VERSION 5.7 ;
  NOWIREEXTENSIONATPIN ON ;
  DIVIDERCHAR "/" ;
  BUSBITCHARS "[]" ;
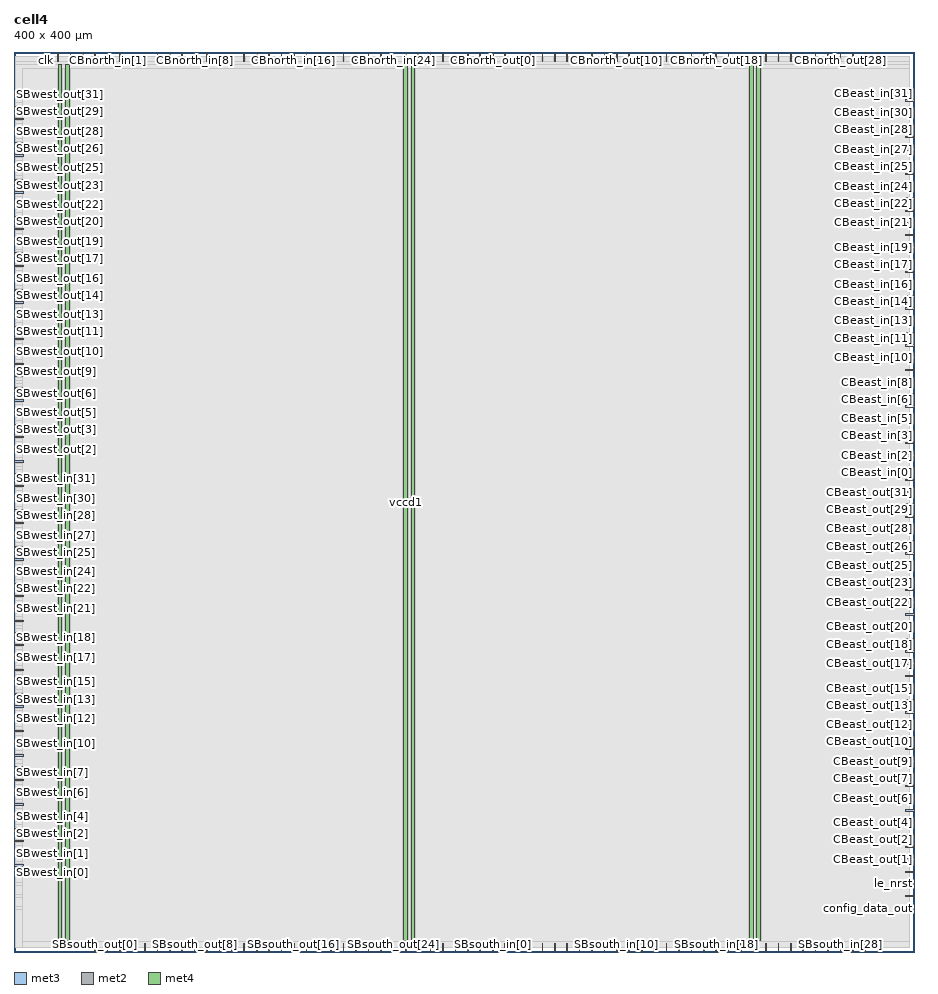
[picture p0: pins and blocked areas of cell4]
MACRO cell4
  CLASS BLOCK ;
  FOREIGN cell4 ;
  ORIGIN 0.000 0.000 ;
  SIZE 400.000 BY 400.000 ;
  PIN CBeast_in[0]
    DIRECTION INPUT ;
    USE SIGNAL ;
    ANTENNAGATEAREA 0.647700 ;
    ANTENNADIFFAREA 0.434700 ;
    PORT
      LAYER met3 ;
        RECT 396.000 209.480 400.000 210.080 ;
    END
  END CBeast_in[0]
  PIN CBeast_in[10]
    DIRECTION INPUT ;
    USE SIGNAL ;
    ANTENNAGATEAREA 0.647700 ;
    ANTENNADIFFAREA 0.434700 ;
    PORT
      LAYER met3 ;
        RECT 396.000 263.880 400.000 264.480 ;
    END
  END CBeast_in[10]
  PIN CBeast_in[11]
    DIRECTION INPUT ;
    USE SIGNAL ;
    ANTENNAGATEAREA 1.082400 ;
    ANTENNADIFFAREA 0.869400 ;
    PORT
      LAYER met3 ;
        RECT 396.000 269.320 400.000 269.920 ;
    END
  END CBeast_in[11]
  PIN CBeast_in[12]
    DIRECTION INPUT ;
    USE SIGNAL ;
    ANTENNAGATEAREA 0.647700 ;
    ANTENNADIFFAREA 0.434700 ;
    PORT
      LAYER met3 ;
        RECT 396.000 274.760 400.000 275.360 ;
    END
  END CBeast_in[12]
  PIN CBeast_in[13]
    DIRECTION INPUT ;
    USE SIGNAL ;
    ANTENNAGATEAREA 0.647700 ;
    ANTENNADIFFAREA 0.434700 ;
    PORT
      LAYER met3 ;
        RECT 396.000 280.200 400.000 280.800 ;
    END
  END CBeast_in[13]
  PIN CBeast_in[14]
    DIRECTION INPUT ;
    USE SIGNAL ;
    ANTENNAGATEAREA 0.647700 ;
    ANTENNADIFFAREA 0.434700 ;
    PORT
      LAYER met3 ;
        RECT 396.000 285.640 400.000 286.240 ;
    END
  END CBeast_in[14]
  PIN CBeast_in[15]
    DIRECTION INPUT ;
    USE SIGNAL ;
    ANTENNAGATEAREA 0.647700 ;
    ANTENNADIFFAREA 0.434700 ;
    PORT
      LAYER met3 ;
        RECT 396.000 291.080 400.000 291.680 ;
    END
  END CBeast_in[15]
  PIN CBeast_in[16]
    DIRECTION INPUT ;
    USE SIGNAL ;
    ANTENNAGATEAREA 1.028400 ;
    ANTENNADIFFAREA 0.869400 ;
    PORT
      LAYER met3 ;
        RECT 396.000 296.520 400.000 297.120 ;
    END
  END CBeast_in[16]
  PIN CBeast_in[17]
    DIRECTION INPUT ;
    USE SIGNAL ;
    ANTENNAGATEAREA 0.593700 ;
    ANTENNADIFFAREA 0.434700 ;
    PORT
      LAYER met3 ;
        RECT 396.000 301.960 400.000 302.560 ;
    END
  END CBeast_in[17]
  PIN CBeast_in[18]
    DIRECTION INPUT ;
    USE SIGNAL ;
    ANTENNAGATEAREA 0.593700 ;
    ANTENNADIFFAREA 0.434700 ;
    PORT
      LAYER met3 ;
        RECT 396.000 307.400 400.000 308.000 ;
    END
  END CBeast_in[18]
  PIN CBeast_in[19]
    DIRECTION INPUT ;
    USE SIGNAL ;
    ANTENNAGATEAREA 0.593700 ;
    ANTENNADIFFAREA 0.434700 ;
    PORT
      LAYER met3 ;
        RECT 396.000 312.840 400.000 313.440 ;
    END
  END CBeast_in[19]
  PIN CBeast_in[1]
    DIRECTION INPUT ;
    USE SIGNAL ;
    ANTENNAGATEAREA 0.647700 ;
    ANTENNADIFFAREA 0.434700 ;
    PORT
      LAYER met3 ;
        RECT 396.000 214.920 400.000 215.520 ;
    END
  END CBeast_in[1]
  PIN CBeast_in[20]
    DIRECTION INPUT ;
    USE SIGNAL ;
    ANTENNAGATEAREA 0.647700 ;
    ANTENNADIFFAREA 0.434700 ;
    PORT
      LAYER met3 ;
        RECT 396.000 318.280 400.000 318.880 ;
    END
  END CBeast_in[20]
  PIN CBeast_in[21]
    DIRECTION INPUT ;
    USE SIGNAL ;
    ANTENNAGATEAREA 0.647700 ;
    ANTENNADIFFAREA 0.434700 ;
    PORT
      LAYER met3 ;
        RECT 396.000 323.720 400.000 324.320 ;
    END
  END CBeast_in[21]
  PIN CBeast_in[22]
    DIRECTION INPUT ;
    USE SIGNAL ;
    ANTENNAGATEAREA 0.593700 ;
    ANTENNADIFFAREA 0.434700 ;
    PORT
      LAYER met3 ;
        RECT 396.000 329.160 400.000 329.760 ;
    END
  END CBeast_in[22]
  PIN CBeast_in[23]
    DIRECTION INPUT ;
    USE SIGNAL ;
    ANTENNAGATEAREA 1.082400 ;
    ANTENNADIFFAREA 0.869400 ;
    PORT
      LAYER met3 ;
        RECT 396.000 334.600 400.000 335.200 ;
    END
  END CBeast_in[23]
  PIN CBeast_in[24]
    DIRECTION INPUT ;
    USE SIGNAL ;
    ANTENNAGATEAREA 0.647700 ;
    ANTENNADIFFAREA 0.434700 ;
    PORT
      LAYER met3 ;
        RECT 396.000 340.040 400.000 340.640 ;
    END
  END CBeast_in[24]
  PIN CBeast_in[25]
    DIRECTION INPUT ;
    USE SIGNAL ;
    ANTENNAGATEAREA 0.647700 ;
    ANTENNADIFFAREA 0.434700 ;
    PORT
      LAYER met3 ;
        RECT 396.000 345.480 400.000 346.080 ;
    END
  END CBeast_in[25]
  PIN CBeast_in[26]
    DIRECTION INPUT ;
    USE SIGNAL ;
    ANTENNAGATEAREA 0.647700 ;
    ANTENNADIFFAREA 0.434700 ;
    PORT
      LAYER met3 ;
        RECT 396.000 350.920 400.000 351.520 ;
    END
  END CBeast_in[26]
  PIN CBeast_in[27]
    DIRECTION INPUT ;
    USE SIGNAL ;
    ANTENNAGATEAREA 0.593700 ;
    ANTENNADIFFAREA 0.434700 ;
    PORT
      LAYER met3 ;
        RECT 396.000 356.360 400.000 356.960 ;
    END
  END CBeast_in[27]
  PIN CBeast_in[28]
    DIRECTION INPUT ;
    USE SIGNAL ;
    ANTENNAGATEAREA 0.593700 ;
    ANTENNADIFFAREA 0.434700 ;
    PORT
      LAYER met3 ;
        RECT 396.000 361.800 400.000 362.400 ;
    END
  END CBeast_in[28]
  PIN CBeast_in[29]
    DIRECTION INPUT ;
    USE SIGNAL ;
    ANTENNAGATEAREA 0.593700 ;
    ANTENNADIFFAREA 0.434700 ;
    PORT
      LAYER met3 ;
        RECT 396.000 367.240 400.000 367.840 ;
    END
  END CBeast_in[29]
  PIN CBeast_in[2]
    DIRECTION INPUT ;
    USE SIGNAL ;
    ANTENNAGATEAREA 0.647700 ;
    ANTENNADIFFAREA 0.434700 ;
    PORT
      LAYER met3 ;
        RECT 396.000 220.360 400.000 220.960 ;
    END
  END CBeast_in[2]
  PIN CBeast_in[30]
    DIRECTION INPUT ;
    USE SIGNAL ;
    ANTENNAGATEAREA 0.647700 ;
    ANTENNADIFFAREA 0.434700 ;
    PORT
      LAYER met3 ;
        RECT 396.000 372.680 400.000 373.280 ;
    END
  END CBeast_in[30]
  PIN CBeast_in[31]
    DIRECTION INPUT ;
    USE SIGNAL ;
    ANTENNAGATEAREA 0.593700 ;
    ANTENNADIFFAREA 0.434700 ;
    PORT
      LAYER met3 ;
        RECT 396.000 378.120 400.000 378.720 ;
    END
  END CBeast_in[31]
  PIN CBeast_in[3]
    DIRECTION INPUT ;
    USE SIGNAL ;
    ANTENNAGATEAREA 0.647700 ;
    ANTENNADIFFAREA 0.434700 ;
    PORT
      LAYER met3 ;
        RECT 396.000 225.800 400.000 226.400 ;
    END
  END CBeast_in[3]
  PIN CBeast_in[4]
    DIRECTION INPUT ;
    USE SIGNAL ;
    ANTENNAGATEAREA 0.647700 ;
    ANTENNADIFFAREA 0.434700 ;
    PORT
      LAYER met3 ;
        RECT 396.000 231.240 400.000 231.840 ;
    END
  END CBeast_in[4]
  PIN CBeast_in[5]
    DIRECTION INPUT ;
    USE SIGNAL ;
    ANTENNAGATEAREA 0.647700 ;
    ANTENNADIFFAREA 0.434700 ;
    PORT
      LAYER met3 ;
        RECT 396.000 236.680 400.000 237.280 ;
    END
  END CBeast_in[5]
  PIN CBeast_in[6]
    DIRECTION INPUT ;
    USE SIGNAL ;
    ANTENNAGATEAREA 0.647700 ;
    ANTENNADIFFAREA 0.434700 ;
    PORT
      LAYER met3 ;
        RECT 396.000 242.120 400.000 242.720 ;
    END
  END CBeast_in[6]
  PIN CBeast_in[7]
    DIRECTION INPUT ;
    USE SIGNAL ;
    ANTENNAGATEAREA 0.647700 ;
    ANTENNADIFFAREA 0.434700 ;
    PORT
      LAYER met3 ;
        RECT 396.000 247.560 400.000 248.160 ;
    END
  END CBeast_in[7]
  PIN CBeast_in[8]
    DIRECTION INPUT ;
    USE SIGNAL ;
    ANTENNAGATEAREA 0.647700 ;
    ANTENNADIFFAREA 0.434700 ;
    PORT
      LAYER met3 ;
        RECT 396.000 253.000 400.000 253.600 ;
    END
  END CBeast_in[8]
  PIN CBeast_in[9]
    DIRECTION INPUT ;
    USE SIGNAL ;
    ANTENNAGATEAREA 0.647700 ;
    ANTENNADIFFAREA 0.434700 ;
    PORT
      LAYER met3 ;
        RECT 396.000 258.440 400.000 259.040 ;
    END
  END CBeast_in[9]
  PIN CBeast_out[0]
    DIRECTION OUTPUT ;
    USE SIGNAL ;
    ANTENNADIFFAREA 0.445500 ;
    PORT
      LAYER met3 ;
        RECT 396.000 35.400 400.000 36.000 ;
    END
  END CBeast_out[0]
  PIN CBeast_out[10]
    DIRECTION OUTPUT ;
    USE SIGNAL ;
    ANTENNADIFFAREA 0.445500 ;
    PORT
      LAYER met3 ;
        RECT 396.000 89.800 400.000 90.400 ;
    END
  END CBeast_out[10]
  PIN CBeast_out[11]
    DIRECTION OUTPUT ;
    USE SIGNAL ;
    ANTENNADIFFAREA 0.445500 ;
    PORT
      LAYER met3 ;
        RECT 396.000 95.240 400.000 95.840 ;
    END
  END CBeast_out[11]
  PIN CBeast_out[12]
    DIRECTION OUTPUT ;
    USE SIGNAL ;
    ANTENNADIFFAREA 0.445500 ;
    PORT
      LAYER met3 ;
        RECT 396.000 100.680 400.000 101.280 ;
    END
  END CBeast_out[12]
  PIN CBeast_out[13]
    DIRECTION OUTPUT ;
    USE SIGNAL ;
    ANTENNADIFFAREA 0.445500 ;
    PORT
      LAYER met3 ;
        RECT 396.000 106.120 400.000 106.720 ;
    END
  END CBeast_out[13]
  PIN CBeast_out[14]
    DIRECTION OUTPUT ;
    USE SIGNAL ;
    ANTENNADIFFAREA 0.445500 ;
    PORT
      LAYER met3 ;
        RECT 396.000 111.560 400.000 112.160 ;
    END
  END CBeast_out[14]
  PIN CBeast_out[15]
    DIRECTION OUTPUT ;
    USE SIGNAL ;
    ANTENNADIFFAREA 0.445500 ;
    PORT
      LAYER met3 ;
        RECT 396.000 117.000 400.000 117.600 ;
    END
  END CBeast_out[15]
  PIN CBeast_out[16]
    DIRECTION OUTPUT ;
    USE SIGNAL ;
    ANTENNADIFFAREA 0.445500 ;
    PORT
      LAYER met3 ;
        RECT 396.000 122.440 400.000 123.040 ;
    END
  END CBeast_out[16]
  PIN CBeast_out[17]
    DIRECTION OUTPUT ;
    USE SIGNAL ;
    ANTENNADIFFAREA 0.445500 ;
    PORT
      LAYER met3 ;
        RECT 396.000 127.880 400.000 128.480 ;
    END
  END CBeast_out[17]
  PIN CBeast_out[18]
    DIRECTION OUTPUT ;
    USE SIGNAL ;
    ANTENNADIFFAREA 0.445500 ;
    PORT
      LAYER met3 ;
        RECT 396.000 133.320 400.000 133.920 ;
    END
  END CBeast_out[18]
  PIN CBeast_out[19]
    DIRECTION OUTPUT ;
    USE SIGNAL ;
    ANTENNADIFFAREA 0.445500 ;
    PORT
      LAYER met3 ;
        RECT 396.000 138.760 400.000 139.360 ;
    END
  END CBeast_out[19]
  PIN CBeast_out[1]
    DIRECTION OUTPUT ;
    USE SIGNAL ;
    ANTENNADIFFAREA 0.445500 ;
    PORT
      LAYER met3 ;
        RECT 396.000 40.840 400.000 41.440 ;
    END
  END CBeast_out[1]
  PIN CBeast_out[20]
    DIRECTION OUTPUT ;
    USE SIGNAL ;
    ANTENNADIFFAREA 0.445500 ;
    PORT
      LAYER met3 ;
        RECT 396.000 144.200 400.000 144.800 ;
    END
  END CBeast_out[20]
  PIN CBeast_out[21]
    DIRECTION OUTPUT ;
    USE SIGNAL ;
    ANTENNADIFFAREA 0.445500 ;
    PORT
      LAYER met3 ;
        RECT 396.000 149.640 400.000 150.240 ;
    END
  END CBeast_out[21]
  PIN CBeast_out[22]
    DIRECTION OUTPUT ;
    USE SIGNAL ;
    ANTENNADIFFAREA 0.445500 ;
    PORT
      LAYER met3 ;
        RECT 396.000 155.080 400.000 155.680 ;
    END
  END CBeast_out[22]
  PIN CBeast_out[23]
    DIRECTION OUTPUT ;
    USE SIGNAL ;
    ANTENNADIFFAREA 0.445500 ;
    PORT
      LAYER met3 ;
        RECT 396.000 160.520 400.000 161.120 ;
    END
  END CBeast_out[23]
  PIN CBeast_out[24]
    DIRECTION OUTPUT ;
    USE SIGNAL ;
    ANTENNADIFFAREA 0.445500 ;
    PORT
      LAYER met3 ;
        RECT 396.000 165.960 400.000 166.560 ;
    END
  END CBeast_out[24]
  PIN CBeast_out[25]
    DIRECTION OUTPUT ;
    USE SIGNAL ;
    ANTENNADIFFAREA 0.445500 ;
    PORT
      LAYER met3 ;
        RECT 396.000 171.400 400.000 172.000 ;
    END
  END CBeast_out[25]
  PIN CBeast_out[26]
    DIRECTION OUTPUT ;
    USE SIGNAL ;
    ANTENNADIFFAREA 0.445500 ;
    PORT
      LAYER met3 ;
        RECT 396.000 176.840 400.000 177.440 ;
    END
  END CBeast_out[26]
  PIN CBeast_out[27]
    DIRECTION OUTPUT ;
    USE SIGNAL ;
    ANTENNADIFFAREA 0.445500 ;
    PORT
      LAYER met3 ;
        RECT 396.000 182.280 400.000 182.880 ;
    END
  END CBeast_out[27]
  PIN CBeast_out[28]
    DIRECTION OUTPUT ;
    USE SIGNAL ;
    ANTENNADIFFAREA 0.445500 ;
    PORT
      LAYER met3 ;
        RECT 396.000 187.720 400.000 188.320 ;
    END
  END CBeast_out[28]
  PIN CBeast_out[29]
    DIRECTION OUTPUT ;
    USE SIGNAL ;
    ANTENNADIFFAREA 0.445500 ;
    PORT
      LAYER met3 ;
        RECT 396.000 193.160 400.000 193.760 ;
    END
  END CBeast_out[29]
  PIN CBeast_out[2]
    DIRECTION OUTPUT ;
    USE SIGNAL ;
    ANTENNADIFFAREA 0.445500 ;
    PORT
      LAYER met3 ;
        RECT 396.000 46.280 400.000 46.880 ;
    END
  END CBeast_out[2]
  PIN CBeast_out[30]
    DIRECTION OUTPUT ;
    USE SIGNAL ;
    ANTENNADIFFAREA 0.445500 ;
    PORT
      LAYER met3 ;
        RECT 396.000 198.600 400.000 199.200 ;
    END
  END CBeast_out[30]
  PIN CBeast_out[31]
    DIRECTION OUTPUT ;
    USE SIGNAL ;
    ANTENNADIFFAREA 0.445500 ;
    PORT
      LAYER met3 ;
        RECT 396.000 204.040 400.000 204.640 ;
    END
  END CBeast_out[31]
  PIN CBeast_out[3]
    DIRECTION OUTPUT ;
    USE SIGNAL ;
    ANTENNADIFFAREA 0.445500 ;
    PORT
      LAYER met3 ;
        RECT 396.000 51.720 400.000 52.320 ;
    END
  END CBeast_out[3]
  PIN CBeast_out[4]
    DIRECTION OUTPUT ;
    USE SIGNAL ;
    ANTENNADIFFAREA 0.445500 ;
    PORT
      LAYER met3 ;
        RECT 396.000 57.160 400.000 57.760 ;
    END
  END CBeast_out[4]
  PIN CBeast_out[5]
    DIRECTION OUTPUT ;
    USE SIGNAL ;
    ANTENNADIFFAREA 0.445500 ;
    PORT
      LAYER met3 ;
        RECT 396.000 62.600 400.000 63.200 ;
    END
  END CBeast_out[5]
  PIN CBeast_out[6]
    DIRECTION OUTPUT ;
    USE SIGNAL ;
    ANTENNADIFFAREA 0.445500 ;
    PORT
      LAYER met3 ;
        RECT 396.000 68.040 400.000 68.640 ;
    END
  END CBeast_out[6]
  PIN CBeast_out[7]
    DIRECTION OUTPUT ;
    USE SIGNAL ;
    ANTENNADIFFAREA 0.445500 ;
    PORT
      LAYER met3 ;
        RECT 396.000 73.480 400.000 74.080 ;
    END
  END CBeast_out[7]
  PIN CBeast_out[8]
    DIRECTION OUTPUT ;
    USE SIGNAL ;
    ANTENNADIFFAREA 0.445500 ;
    PORT
      LAYER met3 ;
        RECT 396.000 78.920 400.000 79.520 ;
    END
  END CBeast_out[8]
  PIN CBeast_out[9]
    DIRECTION OUTPUT ;
    USE SIGNAL ;
    ANTENNADIFFAREA 0.445500 ;
    PORT
      LAYER met3 ;
        RECT 396.000 84.360 400.000 84.960 ;
    END
  END CBeast_out[9]
  PIN CBnorth_in[0]
    DIRECTION INPUT ;
    USE SIGNAL ;
    ANTENNAGATEAREA 0.593700 ;
    ANTENNADIFFAREA 0.434700 ;
    PORT
      LAYER met2 ;
        RECT 35.970 396.000 36.250 400.000 ;
    END
  END CBnorth_in[0]
  PIN CBnorth_in[10]
    DIRECTION INPUT ;
    USE SIGNAL ;
    ANTENNAGATEAREA 0.593700 ;
    ANTENNADIFFAREA 0.434700 ;
    PORT
      LAYER met2 ;
        RECT 91.170 396.000 91.450 400.000 ;
    END
  END CBnorth_in[10]
  PIN CBnorth_in[11]
    DIRECTION INPUT ;
    USE SIGNAL ;
    ANTENNAGATEAREA 1.028400 ;
    ANTENNADIFFAREA 0.869400 ;
    PORT
      LAYER met2 ;
        RECT 96.690 396.000 96.970 400.000 ;
    END
  END CBnorth_in[11]
  PIN CBnorth_in[12]
    DIRECTION INPUT ;
    USE SIGNAL ;
    ANTENNAGATEAREA 0.593700 ;
    ANTENNADIFFAREA 0.434700 ;
    PORT
      LAYER met2 ;
        RECT 102.210 396.000 102.490 400.000 ;
    END
  END CBnorth_in[12]
  PIN CBnorth_in[13]
    DIRECTION INPUT ;
    USE SIGNAL ;
    ANTENNAGATEAREA 0.593700 ;
    ANTENNADIFFAREA 0.434700 ;
    PORT
      LAYER met2 ;
        RECT 107.730 396.000 108.010 400.000 ;
    END
  END CBnorth_in[13]
  PIN CBnorth_in[14]
    DIRECTION INPUT ;
    USE SIGNAL ;
    ANTENNAGATEAREA 0.593700 ;
    ANTENNADIFFAREA 0.434700 ;
    PORT
      LAYER met2 ;
        RECT 113.250 396.000 113.530 400.000 ;
    END
  END CBnorth_in[14]
  PIN CBnorth_in[15]
    DIRECTION INPUT ;
    USE SIGNAL ;
    ANTENNAGATEAREA 0.593700 ;
    ANTENNADIFFAREA 0.434700 ;
    PORT
      LAYER met2 ;
        RECT 118.770 396.000 119.050 400.000 ;
    END
  END CBnorth_in[15]
  PIN CBnorth_in[16]
    DIRECTION INPUT ;
    USE SIGNAL ;
    ANTENNAGATEAREA 0.647700 ;
    ANTENNADIFFAREA 0.434700 ;
    PORT
      LAYER met2 ;
        RECT 124.290 396.000 124.570 400.000 ;
    END
  END CBnorth_in[16]
  PIN CBnorth_in[17]
    DIRECTION INPUT ;
    USE SIGNAL ;
    ANTENNAGATEAREA 0.647700 ;
    ANTENNADIFFAREA 0.434700 ;
    PORT
      LAYER met2 ;
        RECT 129.810 396.000 130.090 400.000 ;
    END
  END CBnorth_in[17]
  PIN CBnorth_in[18]
    DIRECTION INPUT ;
    USE SIGNAL ;
    ANTENNAGATEAREA 0.647700 ;
    ANTENNADIFFAREA 0.434700 ;
    PORT
      LAYER met2 ;
        RECT 135.330 396.000 135.610 400.000 ;
    END
  END CBnorth_in[18]
  PIN CBnorth_in[19]
    DIRECTION INPUT ;
    USE SIGNAL ;
    ANTENNAGATEAREA 0.647700 ;
    ANTENNADIFFAREA 0.434700 ;
    PORT
      LAYER met2 ;
        RECT 140.850 396.000 141.130 400.000 ;
    END
  END CBnorth_in[19]
  PIN CBnorth_in[1]
    DIRECTION INPUT ;
    USE SIGNAL ;
    ANTENNAGATEAREA 0.593700 ;
    ANTENNADIFFAREA 0.434700 ;
    PORT
      LAYER met2 ;
        RECT 41.490 396.000 41.770 400.000 ;
    END
  END CBnorth_in[1]
  PIN CBnorth_in[20]
    DIRECTION INPUT ;
    USE SIGNAL ;
    ANTENNAGATEAREA 0.647700 ;
    ANTENNADIFFAREA 0.434700 ;
    PORT
      LAYER met2 ;
        RECT 146.370 396.000 146.650 400.000 ;
    END
  END CBnorth_in[20]
  PIN CBnorth_in[21]
    DIRECTION INPUT ;
    USE SIGNAL ;
    ANTENNAGATEAREA 0.647700 ;
    ANTENNADIFFAREA 0.434700 ;
    PORT
      LAYER met2 ;
        RECT 151.890 396.000 152.170 400.000 ;
    END
  END CBnorth_in[21]
  PIN CBnorth_in[22]
    DIRECTION INPUT ;
    USE SIGNAL ;
    ANTENNAGATEAREA 0.647700 ;
    ANTENNADIFFAREA 0.434700 ;
    PORT
      LAYER met2 ;
        RECT 157.410 396.000 157.690 400.000 ;
    END
  END CBnorth_in[22]
  PIN CBnorth_in[23]
    DIRECTION INPUT ;
    USE SIGNAL ;
    ANTENNAGATEAREA 0.647700 ;
    ANTENNADIFFAREA 0.434700 ;
    PORT
      LAYER met2 ;
        RECT 162.930 396.000 163.210 400.000 ;
    END
  END CBnorth_in[23]
  PIN CBnorth_in[24]
    DIRECTION INPUT ;
    USE SIGNAL ;
    ANTENNAGATEAREA 0.593700 ;
    ANTENNADIFFAREA 0.434700 ;
    PORT
      LAYER met2 ;
        RECT 168.450 396.000 168.730 400.000 ;
    END
  END CBnorth_in[24]
  PIN CBnorth_in[25]
    DIRECTION INPUT ;
    USE SIGNAL ;
    ANTENNAGATEAREA 0.593700 ;
    ANTENNADIFFAREA 0.434700 ;
    PORT
      LAYER met2 ;
        RECT 173.970 396.000 174.250 400.000 ;
    END
  END CBnorth_in[25]
  PIN CBnorth_in[26]
    DIRECTION INPUT ;
    USE SIGNAL ;
    ANTENNAGATEAREA 0.593700 ;
    ANTENNADIFFAREA 0.434700 ;
    PORT
      LAYER met2 ;
        RECT 179.490 396.000 179.770 400.000 ;
    END
  END CBnorth_in[26]
  PIN CBnorth_in[27]
    DIRECTION INPUT ;
    USE SIGNAL ;
    ANTENNAGATEAREA 0.593700 ;
    ANTENNADIFFAREA 0.434700 ;
    PORT
      LAYER met2 ;
        RECT 185.010 396.000 185.290 400.000 ;
    END
  END CBnorth_in[27]
  PIN CBnorth_in[28]
    DIRECTION INPUT ;
    USE SIGNAL ;
    ANTENNAGATEAREA 0.647700 ;
    ANTENNADIFFAREA 0.434700 ;
    PORT
      LAYER met2 ;
        RECT 190.530 396.000 190.810 400.000 ;
    END
  END CBnorth_in[28]
  PIN CBnorth_in[29]
    DIRECTION INPUT ;
    USE SIGNAL ;
    ANTENNAGATEAREA 0.593700 ;
    ANTENNADIFFAREA 0.434700 ;
    PORT
      LAYER met2 ;
        RECT 196.050 396.000 196.330 400.000 ;
    END
  END CBnorth_in[29]
  PIN CBnorth_in[2]
    DIRECTION INPUT ;
    USE SIGNAL ;
    ANTENNAGATEAREA 0.593700 ;
    ANTENNADIFFAREA 0.434700 ;
    PORT
      LAYER met2 ;
        RECT 47.010 396.000 47.290 400.000 ;
    END
  END CBnorth_in[2]
  PIN CBnorth_in[30]
    DIRECTION INPUT ;
    USE SIGNAL ;
    ANTENNAGATEAREA 0.593700 ;
    ANTENNADIFFAREA 0.434700 ;
    PORT
      LAYER met2 ;
        RECT 201.570 396.000 201.850 400.000 ;
    END
  END CBnorth_in[30]
  PIN CBnorth_in[31]
    DIRECTION INPUT ;
    USE SIGNAL ;
    ANTENNAGATEAREA 0.593700 ;
    ANTENNADIFFAREA 0.434700 ;
    PORT
      LAYER met2 ;
        RECT 207.090 396.000 207.370 400.000 ;
    END
  END CBnorth_in[31]
  PIN CBnorth_in[3]
    DIRECTION INPUT ;
    USE SIGNAL ;
    ANTENNAGATEAREA 0.593700 ;
    ANTENNADIFFAREA 0.434700 ;
    PORT
      LAYER met2 ;
        RECT 52.530 396.000 52.810 400.000 ;
    END
  END CBnorth_in[3]
  PIN CBnorth_in[4]
    DIRECTION INPUT ;
    USE SIGNAL ;
    ANTENNAGATEAREA 0.647700 ;
    ANTENNADIFFAREA 0.434700 ;
    PORT
      LAYER met2 ;
        RECT 58.050 396.000 58.330 400.000 ;
    END
  END CBnorth_in[4]
  PIN CBnorth_in[5]
    DIRECTION INPUT ;
    USE SIGNAL ;
    ANTENNAGATEAREA 0.647700 ;
    ANTENNADIFFAREA 0.434700 ;
    PORT
      LAYER met2 ;
        RECT 63.570 395.860 63.850 400.000 ;
    END
  END CBnorth_in[5]
  PIN CBnorth_in[6]
    DIRECTION INPUT ;
    USE SIGNAL ;
    ANTENNAGATEAREA 0.593700 ;
    ANTENNADIFFAREA 0.434700 ;
    PORT
      LAYER met2 ;
        RECT 69.090 396.000 69.370 400.000 ;
    END
  END CBnorth_in[6]
  PIN CBnorth_in[7]
    DIRECTION INPUT ;
    USE SIGNAL ;
    ANTENNAGATEAREA 0.593700 ;
    ANTENNADIFFAREA 0.434700 ;
    PORT
      LAYER met2 ;
        RECT 74.610 396.000 74.890 400.000 ;
    END
  END CBnorth_in[7]
  PIN CBnorth_in[8]
    DIRECTION INPUT ;
    USE SIGNAL ;
    ANTENNAGATEAREA 0.593700 ;
    ANTENNADIFFAREA 0.434700 ;
    PORT
      LAYER met2 ;
        RECT 80.130 396.000 80.410 400.000 ;
    END
  END CBnorth_in[8]
  PIN CBnorth_in[9]
    DIRECTION INPUT ;
    USE SIGNAL ;
    ANTENNAGATEAREA 0.593700 ;
    ANTENNADIFFAREA 0.434700 ;
    PORT
      LAYER met2 ;
        RECT 85.650 396.000 85.930 400.000 ;
    END
  END CBnorth_in[9]
  PIN CBnorth_out[0]
    DIRECTION OUTPUT ;
    USE SIGNAL ;
    ANTENNADIFFAREA 0.445500 ;
    PORT
      LAYER met2 ;
        RECT 212.610 396.000 212.890 400.000 ;
    END
  END CBnorth_out[0]
  PIN CBnorth_out[10]
    DIRECTION OUTPUT ;
    USE SIGNAL ;
    ANTENNADIFFAREA 0.445500 ;
    PORT
      LAYER met2 ;
        RECT 267.810 396.000 268.090 400.000 ;
    END
  END CBnorth_out[10]
  PIN CBnorth_out[11]
    DIRECTION OUTPUT ;
    USE SIGNAL ;
    ANTENNADIFFAREA 0.445500 ;
    PORT
      LAYER met2 ;
        RECT 273.330 396.000 273.610 400.000 ;
    END
  END CBnorth_out[11]
  PIN CBnorth_out[12]
    DIRECTION OUTPUT ;
    USE SIGNAL ;
    ANTENNADIFFAREA 0.445500 ;
    PORT
      LAYER met2 ;
        RECT 278.850 396.000 279.130 400.000 ;
    END
  END CBnorth_out[12]
  PIN CBnorth_out[13]
    DIRECTION OUTPUT ;
    USE SIGNAL ;
    ANTENNADIFFAREA 0.445500 ;
    PORT
      LAYER met2 ;
        RECT 284.370 396.000 284.650 400.000 ;
    END
  END CBnorth_out[13]
  PIN CBnorth_out[14]
    DIRECTION OUTPUT ;
    USE SIGNAL ;
    ANTENNADIFFAREA 0.445500 ;
    PORT
      LAYER met2 ;
        RECT 289.890 396.000 290.170 400.000 ;
    END
  END CBnorth_out[14]
  PIN CBnorth_out[15]
    DIRECTION OUTPUT ;
    USE SIGNAL ;
    ANTENNADIFFAREA 0.445500 ;
    PORT
      LAYER met2 ;
        RECT 295.410 396.000 295.690 400.000 ;
    END
  END CBnorth_out[15]
  PIN CBnorth_out[16]
    DIRECTION OUTPUT ;
    USE SIGNAL ;
    ANTENNADIFFAREA 0.445500 ;
    PORT
      LAYER met2 ;
        RECT 300.930 396.000 301.210 400.000 ;
    END
  END CBnorth_out[16]
  PIN CBnorth_out[17]
    DIRECTION OUTPUT ;
    USE SIGNAL ;
    ANTENNADIFFAREA 0.445500 ;
    PORT
      LAYER met2 ;
        RECT 306.450 396.000 306.730 400.000 ;
    END
  END CBnorth_out[17]
  PIN CBnorth_out[18]
    DIRECTION OUTPUT ;
    USE SIGNAL ;
    ANTENNADIFFAREA 0.445500 ;
    PORT
      LAYER met2 ;
        RECT 311.970 396.000 312.250 400.000 ;
    END
  END CBnorth_out[18]
  PIN CBnorth_out[19]
    DIRECTION OUTPUT ;
    USE SIGNAL ;
    ANTENNADIFFAREA 0.445500 ;
    PORT
      LAYER met2 ;
        RECT 317.490 396.000 317.770 400.000 ;
    END
  END CBnorth_out[19]
  PIN CBnorth_out[1]
    DIRECTION OUTPUT ;
    USE SIGNAL ;
    ANTENNADIFFAREA 0.445500 ;
    PORT
      LAYER met2 ;
        RECT 218.130 396.000 218.410 400.000 ;
    END
  END CBnorth_out[1]
  PIN CBnorth_out[20]
    DIRECTION OUTPUT ;
    USE SIGNAL ;
    ANTENNADIFFAREA 0.445500 ;
    PORT
      LAYER met2 ;
        RECT 323.010 396.000 323.290 400.000 ;
    END
  END CBnorth_out[20]
  PIN CBnorth_out[21]
    DIRECTION OUTPUT ;
    USE SIGNAL ;
    ANTENNADIFFAREA 0.445500 ;
    PORT
      LAYER met2 ;
        RECT 328.530 396.000 328.810 400.000 ;
    END
  END CBnorth_out[21]
  PIN CBnorth_out[22]
    DIRECTION OUTPUT ;
    USE SIGNAL ;
    ANTENNADIFFAREA 0.445500 ;
    PORT
      LAYER met2 ;
        RECT 334.050 396.000 334.330 400.000 ;
    END
  END CBnorth_out[22]
  PIN CBnorth_out[23]
    DIRECTION OUTPUT ;
    USE SIGNAL ;
    ANTENNADIFFAREA 0.445500 ;
    PORT
      LAYER met2 ;
        RECT 339.570 396.000 339.850 400.000 ;
    END
  END CBnorth_out[23]
  PIN CBnorth_out[24]
    DIRECTION OUTPUT ;
    USE SIGNAL ;
    ANTENNADIFFAREA 0.445500 ;
    PORT
      LAYER met2 ;
        RECT 345.090 396.000 345.370 400.000 ;
    END
  END CBnorth_out[24]
  PIN CBnorth_out[25]
    DIRECTION OUTPUT ;
    USE SIGNAL ;
    ANTENNADIFFAREA 0.445500 ;
    PORT
      LAYER met2 ;
        RECT 350.610 396.000 350.890 400.000 ;
    END
  END CBnorth_out[25]
  PIN CBnorth_out[26]
    DIRECTION OUTPUT ;
    USE SIGNAL ;
    ANTENNADIFFAREA 0.445500 ;
    PORT
      LAYER met2 ;
        RECT 356.130 396.000 356.410 400.000 ;
    END
  END CBnorth_out[26]
  PIN CBnorth_out[27]
    DIRECTION OUTPUT ;
    USE SIGNAL ;
    ANTENNADIFFAREA 0.445500 ;
    PORT
      LAYER met2 ;
        RECT 361.650 396.000 361.930 400.000 ;
    END
  END CBnorth_out[27]
  PIN CBnorth_out[28]
    DIRECTION OUTPUT ;
    USE SIGNAL ;
    ANTENNADIFFAREA 0.445500 ;
    PORT
      LAYER met2 ;
        RECT 367.170 396.000 367.450 400.000 ;
    END
  END CBnorth_out[28]
  PIN CBnorth_out[29]
    DIRECTION OUTPUT ;
    USE SIGNAL ;
    ANTENNADIFFAREA 0.445500 ;
    PORT
      LAYER met2 ;
        RECT 372.690 396.000 372.970 400.000 ;
    END
  END CBnorth_out[29]
  PIN CBnorth_out[2]
    DIRECTION OUTPUT ;
    USE SIGNAL ;
    ANTENNADIFFAREA 0.445500 ;
    PORT
      LAYER met2 ;
        RECT 223.650 396.000 223.930 400.000 ;
    END
  END CBnorth_out[2]
  PIN CBnorth_out[30]
    DIRECTION OUTPUT ;
    USE SIGNAL ;
    ANTENNADIFFAREA 0.445500 ;
    PORT
      LAYER met2 ;
        RECT 378.210 396.000 378.490 400.000 ;
    END
  END CBnorth_out[30]
  PIN CBnorth_out[31]
    DIRECTION OUTPUT ;
    USE SIGNAL ;
    ANTENNADIFFAREA 0.445500 ;
    PORT
      LAYER met2 ;
        RECT 383.730 396.000 384.010 400.000 ;
    END
  END CBnorth_out[31]
  PIN CBnorth_out[3]
    DIRECTION OUTPUT ;
    USE SIGNAL ;
    ANTENNADIFFAREA 0.445500 ;
    PORT
      LAYER met2 ;
        RECT 229.170 396.000 229.450 400.000 ;
    END
  END CBnorth_out[3]
  PIN CBnorth_out[4]
    DIRECTION OUTPUT ;
    USE SIGNAL ;
    ANTENNADIFFAREA 0.445500 ;
    PORT
      LAYER met2 ;
        RECT 234.690 396.000 234.970 400.000 ;
    END
  END CBnorth_out[4]
  PIN CBnorth_out[5]
    DIRECTION OUTPUT ;
    USE SIGNAL ;
    ANTENNADIFFAREA 0.445500 ;
    PORT
      LAYER met2 ;
        RECT 240.210 396.000 240.490 400.000 ;
    END
  END CBnorth_out[5]
  PIN CBnorth_out[6]
    DIRECTION OUTPUT ;
    USE SIGNAL ;
    ANTENNADIFFAREA 0.445500 ;
    PORT
      LAYER met2 ;
        RECT 245.730 396.000 246.010 400.000 ;
    END
  END CBnorth_out[6]
  PIN CBnorth_out[7]
    DIRECTION OUTPUT ;
    USE SIGNAL ;
    ANTENNADIFFAREA 0.445500 ;
    PORT
      LAYER met2 ;
        RECT 251.250 396.000 251.530 400.000 ;
    END
  END CBnorth_out[7]
  PIN CBnorth_out[8]
    DIRECTION OUTPUT ;
    USE SIGNAL ;
    ANTENNADIFFAREA 0.445500 ;
    PORT
      LAYER met2 ;
        RECT 256.770 396.000 257.050 400.000 ;
    END
  END CBnorth_out[8]
  PIN CBnorth_out[9]
    DIRECTION OUTPUT ;
    USE SIGNAL ;
    ANTENNADIFFAREA 0.445500 ;
    PORT
      LAYER met2 ;
        RECT 262.290 396.000 262.570 400.000 ;
    END
  END CBnorth_out[9]
  PIN SBsouth_in[0]
    DIRECTION INPUT ;
    USE SIGNAL ;
    ANTENNAGATEAREA 0.631200 ;
    ANTENNADIFFAREA 0.434700 ;
    PORT
      LAYER met2 ;
        RECT 212.610 0.000 212.890 4.000 ;
    END
  END SBsouth_in[0]
  PIN SBsouth_in[10]
    DIRECTION INPUT ;
    USE SIGNAL ;
    ANTENNAGATEAREA 0.647700 ;
    ANTENNADIFFAREA 0.434700 ;
    PORT
      LAYER met2 ;
        RECT 267.810 0.000 268.090 4.000 ;
    END
  END SBsouth_in[10]
  PIN SBsouth_in[11]
    DIRECTION INPUT ;
    USE SIGNAL ;
    ANTENNAGATEAREA 0.647700 ;
    ANTENNADIFFAREA 0.434700 ;
    PORT
      LAYER met2 ;
        RECT 273.330 0.000 273.610 4.000 ;
    END
  END SBsouth_in[11]
  PIN SBsouth_in[12]
    DIRECTION INPUT ;
    USE SIGNAL ;
    ANTENNAGATEAREA 0.647700 ;
    ANTENNADIFFAREA 0.434700 ;
    PORT
      LAYER met2 ;
        RECT 278.850 0.000 279.130 4.000 ;
    END
  END SBsouth_in[12]
  PIN SBsouth_in[13]
    DIRECTION INPUT ;
    USE SIGNAL ;
    ANTENNAGATEAREA 0.593700 ;
    ANTENNADIFFAREA 0.434700 ;
    PORT
      LAYER met2 ;
        RECT 284.370 0.000 284.650 4.000 ;
    END
  END SBsouth_in[13]
  PIN SBsouth_in[14]
    DIRECTION INPUT ;
    USE SIGNAL ;
    ANTENNAGATEAREA 0.593700 ;
    ANTENNADIFFAREA 0.434700 ;
    PORT
      LAYER met2 ;
        RECT 289.890 0.000 290.170 4.000 ;
    END
  END SBsouth_in[14]
  PIN SBsouth_in[15]
    DIRECTION INPUT ;
    USE SIGNAL ;
    ANTENNAGATEAREA 0.647700 ;
    ANTENNADIFFAREA 0.434700 ;
    PORT
      LAYER met2 ;
        RECT 295.410 0.000 295.690 4.000 ;
    END
  END SBsouth_in[15]
  PIN SBsouth_in[16]
    DIRECTION INPUT ;
    USE SIGNAL ;
    ANTENNAGATEAREA 0.631200 ;
    ANTENNADIFFAREA 0.434700 ;
    PORT
      LAYER met2 ;
        RECT 300.930 0.000 301.210 4.000 ;
    END
  END SBsouth_in[16]
  PIN SBsouth_in[17]
    DIRECTION INPUT ;
    USE SIGNAL ;
    ANTENNAGATEAREA 0.631200 ;
    ANTENNADIFFAREA 0.434700 ;
    PORT
      LAYER met2 ;
        RECT 306.450 0.000 306.730 4.000 ;
    END
  END SBsouth_in[17]
  PIN SBsouth_in[18]
    DIRECTION INPUT ;
    USE SIGNAL ;
    ANTENNAGATEAREA 0.631200 ;
    ANTENNADIFFAREA 0.434700 ;
    PORT
      LAYER met2 ;
        RECT 311.970 0.000 312.250 4.000 ;
    END
  END SBsouth_in[18]
  PIN SBsouth_in[19]
    DIRECTION INPUT ;
    USE SIGNAL ;
    ANTENNAGATEAREA 0.631200 ;
    ANTENNADIFFAREA 0.434700 ;
    PORT
      LAYER met2 ;
        RECT 317.490 0.000 317.770 4.000 ;
    END
  END SBsouth_in[19]
  PIN SBsouth_in[1]
    DIRECTION INPUT ;
    USE SIGNAL ;
    ANTENNAGATEAREA 0.631200 ;
    ANTENNADIFFAREA 0.434700 ;
    PORT
      LAYER met2 ;
        RECT 218.130 0.000 218.410 4.000 ;
    END
  END SBsouth_in[1]
  PIN SBsouth_in[20]
    DIRECTION INPUT ;
    USE SIGNAL ;
    ANTENNAGATEAREA 0.560700 ;
    ANTENNADIFFAREA 0.434700 ;
    PORT
      LAYER met2 ;
        RECT 323.010 0.000 323.290 4.000 ;
    END
  END SBsouth_in[20]
  PIN SBsouth_in[21]
    DIRECTION INPUT ;
    USE SIGNAL ;
    ANTENNAGATEAREA 0.560700 ;
    ANTENNADIFFAREA 0.434700 ;
    PORT
      LAYER met2 ;
        RECT 328.530 0.000 328.810 4.000 ;
    END
  END SBsouth_in[21]
  PIN SBsouth_in[22]
    DIRECTION INPUT ;
    USE SIGNAL ;
    ANTENNAGATEAREA 0.631200 ;
    ANTENNADIFFAREA 0.434700 ;
    PORT
      LAYER met2 ;
        RECT 334.050 0.000 334.330 4.000 ;
    END
  END SBsouth_in[22]
  PIN SBsouth_in[23]
    DIRECTION INPUT ;
    USE SIGNAL ;
    ANTENNAGATEAREA 0.560700 ;
    ANTENNADIFFAREA 0.434700 ;
    PORT
      LAYER met2 ;
        RECT 339.570 0.000 339.850 4.000 ;
    END
  END SBsouth_in[23]
  PIN SBsouth_in[24]
    DIRECTION INPUT ;
    USE SIGNAL ;
    ANTENNAGATEAREA 0.631200 ;
    ANTENNADIFFAREA 0.434700 ;
    PORT
      LAYER met2 ;
        RECT 345.090 0.000 345.370 4.000 ;
    END
  END SBsouth_in[24]
  PIN SBsouth_in[25]
    DIRECTION INPUT ;
    USE SIGNAL ;
    ANTENNAGATEAREA 0.560700 ;
    ANTENNADIFFAREA 0.434700 ;
    PORT
      LAYER met2 ;
        RECT 350.610 0.000 350.890 4.000 ;
    END
  END SBsouth_in[25]
  PIN SBsouth_in[26]
    DIRECTION INPUT ;
    USE SIGNAL ;
    ANTENNAGATEAREA 0.647700 ;
    ANTENNADIFFAREA 0.434700 ;
    PORT
      LAYER met2 ;
        RECT 356.130 0.000 356.410 4.000 ;
    END
  END SBsouth_in[26]
  PIN SBsouth_in[27]
    DIRECTION INPUT ;
    USE SIGNAL ;
    ANTENNAGATEAREA 0.560700 ;
    ANTENNADIFFAREA 0.434700 ;
    PORT
      LAYER met2 ;
        RECT 361.650 0.000 361.930 4.000 ;
    END
  END SBsouth_in[27]
  PIN SBsouth_in[28]
    DIRECTION INPUT ;
    USE SIGNAL ;
    ANTENNAGATEAREA 0.560700 ;
    ANTENNADIFFAREA 0.434700 ;
    PORT
      LAYER met2 ;
        RECT 367.170 0.000 367.450 4.000 ;
    END
  END SBsouth_in[28]
  PIN SBsouth_in[29]
    DIRECTION INPUT ;
    USE SIGNAL ;
    ANTENNAGATEAREA 0.647700 ;
    ANTENNADIFFAREA 0.434700 ;
    PORT
      LAYER met2 ;
        RECT 372.690 0.000 372.970 4.000 ;
    END
  END SBsouth_in[29]
  PIN SBsouth_in[2]
    DIRECTION INPUT ;
    USE SIGNAL ;
    ANTENNAGATEAREA 0.560700 ;
    ANTENNADIFFAREA 0.434700 ;
    PORT
      LAYER met2 ;
        RECT 223.650 0.000 223.930 4.000 ;
    END
  END SBsouth_in[2]
  PIN SBsouth_in[30]
    DIRECTION INPUT ;
    USE SIGNAL ;
    ANTENNAGATEAREA 0.647700 ;
    ANTENNADIFFAREA 0.434700 ;
    PORT
      LAYER met2 ;
        RECT 378.210 0.000 378.490 4.000 ;
    END
  END SBsouth_in[30]
  PIN SBsouth_in[31]
    DIRECTION INPUT ;
    USE SIGNAL ;
    ANTENNAGATEAREA 0.647700 ;
    ANTENNADIFFAREA 0.434700 ;
    PORT
      LAYER met2 ;
        RECT 383.730 0.000 384.010 4.000 ;
    END
  END SBsouth_in[31]
  PIN SBsouth_in[3]
    DIRECTION INPUT ;
    USE SIGNAL ;
    ANTENNAGATEAREA 0.560700 ;
    ANTENNADIFFAREA 0.434700 ;
    PORT
      LAYER met2 ;
        RECT 229.170 0.000 229.450 4.000 ;
    END
  END SBsouth_in[3]
  PIN SBsouth_in[4]
    DIRECTION INPUT ;
    USE SIGNAL ;
    ANTENNAGATEAREA 0.647700 ;
    ANTENNADIFFAREA 0.434700 ;
    PORT
      LAYER met2 ;
        RECT 234.690 0.000 234.970 4.000 ;
    END
  END SBsouth_in[4]
  PIN SBsouth_in[5]
    DIRECTION INPUT ;
    USE SIGNAL ;
    ANTENNAGATEAREA 0.647700 ;
    ANTENNADIFFAREA 0.434700 ;
    PORT
      LAYER met2 ;
        RECT 240.210 0.000 240.490 4.000 ;
    END
  END SBsouth_in[5]
  PIN SBsouth_in[6]
    DIRECTION INPUT ;
    USE SIGNAL ;
    ANTENNAGATEAREA 0.647700 ;
    ANTENNADIFFAREA 0.434700 ;
    PORT
      LAYER met2 ;
        RECT 245.730 0.000 246.010 4.000 ;
    END
  END SBsouth_in[6]
  PIN SBsouth_in[7]
    DIRECTION INPUT ;
    USE SIGNAL ;
    ANTENNAGATEAREA 0.647700 ;
    ANTENNADIFFAREA 0.434700 ;
    PORT
      LAYER met2 ;
        RECT 251.250 0.000 251.530 4.000 ;
    END
  END SBsouth_in[7]
  PIN SBsouth_in[8]
    DIRECTION INPUT ;
    USE SIGNAL ;
    ANTENNAGATEAREA 0.647700 ;
    ANTENNADIFFAREA 0.434700 ;
    PORT
      LAYER met2 ;
        RECT 256.770 0.000 257.050 4.000 ;
    END
  END SBsouth_in[8]
  PIN SBsouth_in[9]
    DIRECTION INPUT ;
    USE SIGNAL ;
    ANTENNAGATEAREA 0.647700 ;
    ANTENNADIFFAREA 0.434700 ;
    PORT
      LAYER met2 ;
        RECT 262.290 0.000 262.570 4.000 ;
    END
  END SBsouth_in[9]
  PIN SBsouth_out[0]
    DIRECTION OUTPUT ;
    USE SIGNAL ;
    ANTENNADIFFAREA 0.445500 ;
    PORT
      LAYER met2 ;
        RECT 35.970 0.000 36.250 4.000 ;
    END
  END SBsouth_out[0]
  PIN SBsouth_out[10]
    DIRECTION OUTPUT ;
    USE SIGNAL ;
    ANTENNADIFFAREA 0.445500 ;
    PORT
      LAYER met2 ;
        RECT 91.170 0.000 91.450 4.000 ;
    END
  END SBsouth_out[10]
  PIN SBsouth_out[11]
    DIRECTION OUTPUT ;
    USE SIGNAL ;
    ANTENNADIFFAREA 0.445500 ;
    PORT
      LAYER met2 ;
        RECT 96.690 0.000 96.970 4.000 ;
    END
  END SBsouth_out[11]
  PIN SBsouth_out[12]
    DIRECTION OUTPUT ;
    USE SIGNAL ;
    ANTENNADIFFAREA 0.445500 ;
    PORT
      LAYER met2 ;
        RECT 102.210 0.000 102.490 4.000 ;
    END
  END SBsouth_out[12]
  PIN SBsouth_out[13]
    DIRECTION OUTPUT ;
    USE SIGNAL ;
    ANTENNADIFFAREA 0.445500 ;
    PORT
      LAYER met2 ;
        RECT 107.730 0.000 108.010 4.000 ;
    END
  END SBsouth_out[13]
  PIN SBsouth_out[14]
    DIRECTION OUTPUT ;
    USE SIGNAL ;
    ANTENNADIFFAREA 0.445500 ;
    PORT
      LAYER met2 ;
        RECT 113.250 0.000 113.530 4.000 ;
    END
  END SBsouth_out[14]
  PIN SBsouth_out[15]
    DIRECTION OUTPUT ;
    USE SIGNAL ;
    ANTENNADIFFAREA 0.445500 ;
    PORT
      LAYER met2 ;
        RECT 118.770 0.000 119.050 4.000 ;
    END
  END SBsouth_out[15]
  PIN SBsouth_out[16]
    DIRECTION OUTPUT ;
    USE SIGNAL ;
    ANTENNADIFFAREA 0.445500 ;
    PORT
      LAYER met2 ;
        RECT 124.290 0.000 124.570 4.000 ;
    END
  END SBsouth_out[16]
  PIN SBsouth_out[17]
    DIRECTION OUTPUT ;
    USE SIGNAL ;
    ANTENNADIFFAREA 0.445500 ;
    PORT
      LAYER met2 ;
        RECT 129.810 0.000 130.090 4.000 ;
    END
  END SBsouth_out[17]
  PIN SBsouth_out[18]
    DIRECTION OUTPUT ;
    USE SIGNAL ;
    ANTENNADIFFAREA 0.445500 ;
    PORT
      LAYER met2 ;
        RECT 135.330 0.000 135.610 4.000 ;
    END
  END SBsouth_out[18]
  PIN SBsouth_out[19]
    DIRECTION OUTPUT ;
    USE SIGNAL ;
    ANTENNADIFFAREA 0.445500 ;
    PORT
      LAYER met2 ;
        RECT 140.850 0.000 141.130 4.000 ;
    END
  END SBsouth_out[19]
  PIN SBsouth_out[1]
    DIRECTION OUTPUT ;
    USE SIGNAL ;
    ANTENNADIFFAREA 0.445500 ;
    PORT
      LAYER met2 ;
        RECT 41.490 0.000 41.770 4.000 ;
    END
  END SBsouth_out[1]
  PIN SBsouth_out[20]
    DIRECTION OUTPUT ;
    USE SIGNAL ;
    ANTENNADIFFAREA 0.445500 ;
    PORT
      LAYER met2 ;
        RECT 146.370 0.000 146.650 4.000 ;
    END
  END SBsouth_out[20]
  PIN SBsouth_out[21]
    DIRECTION OUTPUT ;
    USE SIGNAL ;
    ANTENNADIFFAREA 0.445500 ;
    PORT
      LAYER met2 ;
        RECT 151.890 0.000 152.170 4.000 ;
    END
  END SBsouth_out[21]
  PIN SBsouth_out[22]
    DIRECTION OUTPUT ;
    USE SIGNAL ;
    ANTENNADIFFAREA 0.445500 ;
    PORT
      LAYER met2 ;
        RECT 157.410 0.000 157.690 4.000 ;
    END
  END SBsouth_out[22]
  PIN SBsouth_out[23]
    DIRECTION OUTPUT ;
    USE SIGNAL ;
    ANTENNADIFFAREA 0.445500 ;
    PORT
      LAYER met2 ;
        RECT 162.930 0.000 163.210 4.000 ;
    END
  END SBsouth_out[23]
  PIN SBsouth_out[24]
    DIRECTION OUTPUT ;
    USE SIGNAL ;
    ANTENNADIFFAREA 0.445500 ;
    PORT
      LAYER met2 ;
        RECT 168.450 0.000 168.730 4.000 ;
    END
  END SBsouth_out[24]
  PIN SBsouth_out[25]
    DIRECTION OUTPUT ;
    USE SIGNAL ;
    ANTENNADIFFAREA 0.445500 ;
    PORT
      LAYER met2 ;
        RECT 173.970 0.000 174.250 4.000 ;
    END
  END SBsouth_out[25]
  PIN SBsouth_out[26]
    DIRECTION OUTPUT ;
    USE SIGNAL ;
    ANTENNADIFFAREA 0.445500 ;
    PORT
      LAYER met2 ;
        RECT 179.490 0.000 179.770 4.000 ;
    END
  END SBsouth_out[26]
  PIN SBsouth_out[27]
    DIRECTION OUTPUT ;
    USE SIGNAL ;
    ANTENNADIFFAREA 0.445500 ;
    PORT
      LAYER met2 ;
        RECT 185.010 0.000 185.290 4.000 ;
    END
  END SBsouth_out[27]
  PIN SBsouth_out[28]
    DIRECTION OUTPUT ;
    USE SIGNAL ;
    ANTENNADIFFAREA 0.445500 ;
    PORT
      LAYER met2 ;
        RECT 190.530 0.000 190.810 4.000 ;
    END
  END SBsouth_out[28]
  PIN SBsouth_out[29]
    DIRECTION OUTPUT ;
    USE SIGNAL ;
    ANTENNADIFFAREA 0.445500 ;
    PORT
      LAYER met2 ;
        RECT 196.050 0.000 196.330 4.000 ;
    END
  END SBsouth_out[29]
  PIN SBsouth_out[2]
    DIRECTION OUTPUT ;
    USE SIGNAL ;
    ANTENNADIFFAREA 0.445500 ;
    PORT
      LAYER met2 ;
        RECT 47.010 0.000 47.290 4.000 ;
    END
  END SBsouth_out[2]
  PIN SBsouth_out[30]
    DIRECTION OUTPUT ;
    USE SIGNAL ;
    ANTENNADIFFAREA 0.445500 ;
    PORT
      LAYER met2 ;
        RECT 201.570 0.000 201.850 4.000 ;
    END
  END SBsouth_out[30]
  PIN SBsouth_out[31]
    DIRECTION OUTPUT ;
    USE SIGNAL ;
    ANTENNADIFFAREA 0.445500 ;
    PORT
      LAYER met2 ;
        RECT 207.090 0.000 207.370 4.000 ;
    END
  END SBsouth_out[31]
  PIN SBsouth_out[3]
    DIRECTION OUTPUT ;
    USE SIGNAL ;
    ANTENNADIFFAREA 0.445500 ;
    PORT
      LAYER met2 ;
        RECT 52.530 0.000 52.810 4.000 ;
    END
  END SBsouth_out[3]
  PIN SBsouth_out[4]
    DIRECTION OUTPUT ;
    USE SIGNAL ;
    ANTENNADIFFAREA 0.445500 ;
    PORT
      LAYER met2 ;
        RECT 58.050 0.000 58.330 4.000 ;
    END
  END SBsouth_out[4]
  PIN SBsouth_out[5]
    DIRECTION OUTPUT ;
    USE SIGNAL ;
    ANTENNADIFFAREA 0.445500 ;
    PORT
      LAYER met2 ;
        RECT 63.570 0.000 63.850 4.000 ;
    END
  END SBsouth_out[5]
  PIN SBsouth_out[6]
    DIRECTION OUTPUT ;
    USE SIGNAL ;
    ANTENNADIFFAREA 0.445500 ;
    PORT
      LAYER met2 ;
        RECT 69.090 0.000 69.370 4.000 ;
    END
  END SBsouth_out[6]
  PIN SBsouth_out[7]
    DIRECTION OUTPUT ;
    USE SIGNAL ;
    ANTENNADIFFAREA 0.445500 ;
    PORT
      LAYER met2 ;
        RECT 74.610 0.000 74.890 4.000 ;
    END
  END SBsouth_out[7]
  PIN SBsouth_out[8]
    DIRECTION OUTPUT ;
    USE SIGNAL ;
    ANTENNADIFFAREA 0.445500 ;
    PORT
      LAYER met2 ;
        RECT 80.130 0.000 80.410 4.000 ;
    END
  END SBsouth_out[8]
  PIN SBsouth_out[9]
    DIRECTION OUTPUT ;
    USE SIGNAL ;
    ANTENNADIFFAREA 0.445500 ;
    PORT
      LAYER met2 ;
        RECT 85.650 0.000 85.930 4.000 ;
    END
  END SBsouth_out[9]
  PIN SBwest_in[0]
    DIRECTION INPUT ;
    USE SIGNAL ;
    ANTENNAGATEAREA 0.631200 ;
    ANTENNADIFFAREA 0.434700 ;
    PORT
      LAYER met3 ;
        RECT 0.000 38.120 4.000 38.720 ;
    END
  END SBwest_in[0]
  PIN SBwest_in[10]
    DIRECTION INPUT ;
    USE SIGNAL ;
    ANTENNAGATEAREA 0.631200 ;
    ANTENNADIFFAREA 0.434700 ;
    PORT
      LAYER met3 ;
        RECT 0.000 92.520 4.000 93.120 ;
    END
  END SBwest_in[10]
  PIN SBwest_in[11]
    DIRECTION INPUT ;
    USE SIGNAL ;
    ANTENNAGATEAREA 0.631200 ;
    ANTENNADIFFAREA 0.434700 ;
    PORT
      LAYER met3 ;
        RECT 0.000 97.960 4.000 98.560 ;
    END
  END SBwest_in[11]
  PIN SBwest_in[12]
    DIRECTION INPUT ;
    USE SIGNAL ;
    ANTENNAGATEAREA 0.631200 ;
    ANTENNADIFFAREA 0.434700 ;
    PORT
      LAYER met3 ;
        RECT 0.000 103.400 4.000 104.000 ;
    END
  END SBwest_in[12]
  PIN SBwest_in[13]
    DIRECTION INPUT ;
    USE SIGNAL ;
    ANTENNAGATEAREA 0.631200 ;
    ANTENNADIFFAREA 0.434700 ;
    PORT
      LAYER met3 ;
        RECT 0.000 108.840 4.000 109.440 ;
    END
  END SBwest_in[13]
  PIN SBwest_in[14]
    DIRECTION INPUT ;
    USE SIGNAL ;
    ANTENNAGATEAREA 0.631200 ;
    ANTENNADIFFAREA 0.434700 ;
    PORT
      LAYER met3 ;
        RECT 0.000 114.280 4.000 114.880 ;
    END
  END SBwest_in[14]
  PIN SBwest_in[15]
    DIRECTION INPUT ;
    USE SIGNAL ;
    ANTENNAGATEAREA 0.631200 ;
    ANTENNADIFFAREA 0.434700 ;
    PORT
      LAYER met3 ;
        RECT 0.000 119.720 4.000 120.320 ;
    END
  END SBwest_in[15]
  PIN SBwest_in[16]
    DIRECTION INPUT ;
    USE SIGNAL ;
    ANTENNAGATEAREA 0.560700 ;
    ANTENNADIFFAREA 0.434700 ;
    PORT
      LAYER met3 ;
        RECT 0.000 125.160 4.000 125.760 ;
    END
  END SBwest_in[16]
  PIN SBwest_in[17]
    DIRECTION INPUT ;
    USE SIGNAL ;
    ANTENNAGATEAREA 0.560700 ;
    ANTENNADIFFAREA 0.434700 ;
    PORT
      LAYER met3 ;
        RECT 0.000 130.600 4.000 131.200 ;
    END
  END SBwest_in[17]
  PIN SBwest_in[18]
    DIRECTION INPUT ;
    USE SIGNAL ;
    ANTENNAGATEAREA 0.631200 ;
    ANTENNADIFFAREA 0.434700 ;
    PORT
      LAYER met3 ;
        RECT 0.000 136.040 4.000 136.640 ;
    END
  END SBwest_in[18]
  PIN SBwest_in[19]
    DIRECTION INPUT ;
    USE SIGNAL ;
    ANTENNAGATEAREA 0.560700 ;
    ANTENNADIFFAREA 0.434700 ;
    PORT
      LAYER met3 ;
        RECT 0.000 141.480 4.000 142.080 ;
    END
  END SBwest_in[19]
  PIN SBwest_in[1]
    DIRECTION INPUT ;
    USE SIGNAL ;
    ANTENNAGATEAREA 0.631200 ;
    ANTENNADIFFAREA 0.434700 ;
    PORT
      LAYER met3 ;
        RECT 0.000 43.560 4.000 44.160 ;
    END
  END SBwest_in[1]
  PIN SBwest_in[20]
    DIRECTION INPUT ;
    USE SIGNAL ;
    ANTENNAGATEAREA 0.560700 ;
    ANTENNADIFFAREA 0.434700 ;
    PORT
      LAYER met3 ;
        RECT 0.000 146.920 4.000 147.520 ;
    END
  END SBwest_in[20]
  PIN SBwest_in[21]
    DIRECTION INPUT ;
    USE SIGNAL ;
    ANTENNAGATEAREA 0.631200 ;
    ANTENNADIFFAREA 0.434700 ;
    PORT
      LAYER met3 ;
        RECT 0.000 152.360 4.000 152.960 ;
    END
  END SBwest_in[21]
  PIN SBwest_in[22]
    DIRECTION INPUT ;
    USE SIGNAL ;
    ANTENNAGATEAREA 0.631200 ;
    ANTENNADIFFAREA 0.434700 ;
    PORT
      LAYER met3 ;
        RECT 0.000 157.800 4.000 158.400 ;
    END
  END SBwest_in[22]
  PIN SBwest_in[23]
    DIRECTION INPUT ;
    USE SIGNAL ;
    ANTENNAGATEAREA 0.631200 ;
    ANTENNADIFFAREA 0.434700 ;
    PORT
      LAYER met3 ;
        RECT 0.000 163.240 4.000 163.840 ;
    END
  END SBwest_in[23]
  PIN SBwest_in[24]
    DIRECTION INPUT ;
    USE SIGNAL ;
    ANTENNAGATEAREA 0.631200 ;
    ANTENNADIFFAREA 0.434700 ;
    PORT
      LAYER met3 ;
        RECT 0.000 168.680 4.000 169.280 ;
    END
  END SBwest_in[24]
  PIN SBwest_in[25]
    DIRECTION INPUT ;
    USE SIGNAL ;
    ANTENNAGATEAREA 0.631200 ;
    ANTENNADIFFAREA 0.434700 ;
    PORT
      LAYER met3 ;
        RECT 0.000 174.120 4.000 174.720 ;
    END
  END SBwest_in[25]
  PIN SBwest_in[26]
    DIRECTION INPUT ;
    USE SIGNAL ;
    ANTENNAGATEAREA 0.631200 ;
    ANTENNADIFFAREA 0.434700 ;
    PORT
      LAYER met3 ;
        RECT 0.000 179.560 4.000 180.160 ;
    END
  END SBwest_in[26]
  PIN SBwest_in[27]
    DIRECTION INPUT ;
    USE SIGNAL ;
    ANTENNAGATEAREA 0.631200 ;
    ANTENNADIFFAREA 0.434700 ;
    PORT
      LAYER met3 ;
        RECT 0.000 185.000 4.000 185.600 ;
    END
  END SBwest_in[27]
  PIN SBwest_in[28]
    DIRECTION INPUT ;
    USE SIGNAL ;
    ANTENNAGATEAREA 0.631200 ;
    ANTENNADIFFAREA 0.434700 ;
    PORT
      LAYER met3 ;
        RECT 0.000 190.440 4.000 191.040 ;
    END
  END SBwest_in[28]
  PIN SBwest_in[29]
    DIRECTION INPUT ;
    USE SIGNAL ;
    ANTENNAGATEAREA 0.631200 ;
    ANTENNADIFFAREA 0.434700 ;
    PORT
      LAYER met3 ;
        RECT 0.000 195.880 4.000 196.480 ;
    END
  END SBwest_in[29]
  PIN SBwest_in[2]
    DIRECTION INPUT ;
    USE SIGNAL ;
    ANTENNAGATEAREA 0.631200 ;
    ANTENNADIFFAREA 0.434700 ;
    PORT
      LAYER met3 ;
        RECT 0.000 49.000 4.000 49.600 ;
    END
  END SBwest_in[2]
  PIN SBwest_in[30]
    DIRECTION INPUT ;
    USE SIGNAL ;
    ANTENNAGATEAREA 0.631200 ;
    ANTENNADIFFAREA 0.434700 ;
    PORT
      LAYER met3 ;
        RECT 0.000 201.320 4.000 201.920 ;
    END
  END SBwest_in[30]
  PIN SBwest_in[31]
    DIRECTION INPUT ;
    USE SIGNAL ;
    ANTENNAGATEAREA 0.560700 ;
    ANTENNADIFFAREA 0.434700 ;
    PORT
      LAYER met3 ;
        RECT 0.000 206.760 4.000 207.360 ;
    END
  END SBwest_in[31]
  PIN SBwest_in[3]
    DIRECTION INPUT ;
    USE SIGNAL ;
    ANTENNAGATEAREA 0.631200 ;
    ANTENNADIFFAREA 0.434700 ;
    PORT
      LAYER met3 ;
        RECT 0.000 54.440 4.000 55.040 ;
    END
  END SBwest_in[3]
  PIN SBwest_in[4]
    DIRECTION INPUT ;
    USE SIGNAL ;
    ANTENNAGATEAREA 0.631200 ;
    ANTENNADIFFAREA 0.434700 ;
    PORT
      LAYER met3 ;
        RECT 0.000 59.880 4.000 60.480 ;
    END
  END SBwest_in[4]
  PIN SBwest_in[5]
    DIRECTION INPUT ;
    USE SIGNAL ;
    ANTENNAGATEAREA 0.631200 ;
    ANTENNADIFFAREA 0.434700 ;
    PORT
      LAYER met3 ;
        RECT 0.000 65.320 4.000 65.920 ;
    END
  END SBwest_in[5]
  PIN SBwest_in[6]
    DIRECTION INPUT ;
    USE SIGNAL ;
    ANTENNAGATEAREA 0.631200 ;
    ANTENNADIFFAREA 0.434700 ;
    PORT
      LAYER met3 ;
        RECT 0.000 70.760 4.000 71.360 ;
    END
  END SBwest_in[6]
  PIN SBwest_in[7]
    DIRECTION INPUT ;
    USE SIGNAL ;
    ANTENNAGATEAREA 0.631200 ;
    ANTENNADIFFAREA 0.434700 ;
    PORT
      LAYER met3 ;
        RECT 0.000 76.200 4.000 76.800 ;
    END
  END SBwest_in[7]
  PIN SBwest_in[8]
    DIRECTION INPUT ;
    USE SIGNAL ;
    ANTENNAGATEAREA 0.631200 ;
    ANTENNADIFFAREA 0.434700 ;
    PORT
      LAYER met3 ;
        RECT 0.000 81.640 4.000 82.240 ;
    END
  END SBwest_in[8]
  PIN SBwest_in[9]
    DIRECTION INPUT ;
    USE SIGNAL ;
    ANTENNAGATEAREA 0.631200 ;
    ANTENNADIFFAREA 0.434700 ;
    PORT
      LAYER met3 ;
        RECT 0.000 87.080 4.000 87.680 ;
    END
  END SBwest_in[9]
  PIN SBwest_out[0]
    DIRECTION OUTPUT ;
    USE SIGNAL ;
    ANTENNADIFFAREA 0.445500 ;
    PORT
      LAYER met3 ;
        RECT 0.000 212.200 4.000 212.800 ;
    END
  END SBwest_out[0]
  PIN SBwest_out[10]
    DIRECTION OUTPUT ;
    USE SIGNAL ;
    ANTENNADIFFAREA 0.445500 ;
    PORT
      LAYER met3 ;
        RECT 0.000 266.600 4.000 267.200 ;
    END
  END SBwest_out[10]
  PIN SBwest_out[11]
    DIRECTION OUTPUT ;
    USE SIGNAL ;
    ANTENNADIFFAREA 0.445500 ;
    PORT
      LAYER met3 ;
        RECT 0.000 272.040 4.000 272.640 ;
    END
  END SBwest_out[11]
  PIN SBwest_out[12]
    DIRECTION OUTPUT ;
    USE SIGNAL ;
    ANTENNADIFFAREA 0.445500 ;
    PORT
      LAYER met3 ;
        RECT 0.000 277.480 4.000 278.080 ;
    END
  END SBwest_out[12]
  PIN SBwest_out[13]
    DIRECTION OUTPUT ;
    USE SIGNAL ;
    ANTENNADIFFAREA 0.445500 ;
    PORT
      LAYER met3 ;
        RECT 0.000 282.920 4.000 283.520 ;
    END
  END SBwest_out[13]
  PIN SBwest_out[14]
    DIRECTION OUTPUT ;
    USE SIGNAL ;
    ANTENNADIFFAREA 0.445500 ;
    PORT
      LAYER met3 ;
        RECT 0.000 288.360 4.000 288.960 ;
    END
  END SBwest_out[14]
  PIN SBwest_out[15]
    DIRECTION OUTPUT ;
    USE SIGNAL ;
    ANTENNADIFFAREA 0.445500 ;
    PORT
      LAYER met3 ;
        RECT 0.000 293.800 4.000 294.400 ;
    END
  END SBwest_out[15]
  PIN SBwest_out[16]
    DIRECTION OUTPUT ;
    USE SIGNAL ;
    ANTENNADIFFAREA 0.445500 ;
    PORT
      LAYER met3 ;
        RECT 0.000 299.240 4.000 299.840 ;
    END
  END SBwest_out[16]
  PIN SBwest_out[17]
    DIRECTION OUTPUT ;
    USE SIGNAL ;
    ANTENNADIFFAREA 0.445500 ;
    PORT
      LAYER met3 ;
        RECT 0.000 304.680 4.000 305.280 ;
    END
  END SBwest_out[17]
  PIN SBwest_out[18]
    DIRECTION OUTPUT ;
    USE SIGNAL ;
    ANTENNADIFFAREA 0.445500 ;
    PORT
      LAYER met3 ;
        RECT 0.000 310.120 4.000 310.720 ;
    END
  END SBwest_out[18]
  PIN SBwest_out[19]
    DIRECTION OUTPUT ;
    USE SIGNAL ;
    ANTENNADIFFAREA 0.445500 ;
    PORT
      LAYER met3 ;
        RECT 0.000 315.560 4.000 316.160 ;
    END
  END SBwest_out[19]
  PIN SBwest_out[1]
    DIRECTION OUTPUT ;
    USE SIGNAL ;
    ANTENNADIFFAREA 0.445500 ;
    PORT
      LAYER met3 ;
        RECT 0.000 217.640 4.000 218.240 ;
    END
  END SBwest_out[1]
  PIN SBwest_out[20]
    DIRECTION OUTPUT ;
    USE SIGNAL ;
    ANTENNADIFFAREA 0.445500 ;
    PORT
      LAYER met3 ;
        RECT 0.000 321.000 4.000 321.600 ;
    END
  END SBwest_out[20]
  PIN SBwest_out[21]
    DIRECTION OUTPUT ;
    USE SIGNAL ;
    ANTENNADIFFAREA 0.445500 ;
    PORT
      LAYER met3 ;
        RECT 0.000 326.440 4.000 327.040 ;
    END
  END SBwest_out[21]
  PIN SBwest_out[22]
    DIRECTION OUTPUT ;
    USE SIGNAL ;
    ANTENNADIFFAREA 0.445500 ;
    PORT
      LAYER met3 ;
        RECT 0.000 331.880 4.000 332.480 ;
    END
  END SBwest_out[22]
  PIN SBwest_out[23]
    DIRECTION OUTPUT ;
    USE SIGNAL ;
    ANTENNADIFFAREA 0.445500 ;
    PORT
      LAYER met3 ;
        RECT 0.000 337.320 4.000 337.920 ;
    END
  END SBwest_out[23]
  PIN SBwest_out[24]
    DIRECTION OUTPUT ;
    USE SIGNAL ;
    ANTENNADIFFAREA 0.445500 ;
    PORT
      LAYER met3 ;
        RECT 0.000 342.760 4.000 343.360 ;
    END
  END SBwest_out[24]
  PIN SBwest_out[25]
    DIRECTION OUTPUT ;
    USE SIGNAL ;
    ANTENNADIFFAREA 0.445500 ;
    PORT
      LAYER met3 ;
        RECT 0.000 348.200 4.000 348.800 ;
    END
  END SBwest_out[25]
  PIN SBwest_out[26]
    DIRECTION OUTPUT ;
    USE SIGNAL ;
    ANTENNADIFFAREA 0.445500 ;
    PORT
      LAYER met3 ;
        RECT 0.000 353.640 4.000 354.240 ;
    END
  END SBwest_out[26]
  PIN SBwest_out[27]
    DIRECTION OUTPUT ;
    USE SIGNAL ;
    ANTENNADIFFAREA 0.445500 ;
    PORT
      LAYER met3 ;
        RECT 0.000 359.080 4.000 359.680 ;
    END
  END SBwest_out[27]
  PIN SBwest_out[28]
    DIRECTION OUTPUT ;
    USE SIGNAL ;
    ANTENNADIFFAREA 0.445500 ;
    PORT
      LAYER met3 ;
        RECT 0.000 364.520 4.000 365.120 ;
    END
  END SBwest_out[28]
  PIN SBwest_out[29]
    DIRECTION OUTPUT ;
    USE SIGNAL ;
    ANTENNADIFFAREA 0.445500 ;
    PORT
      LAYER met3 ;
        RECT 0.000 369.960 4.000 370.560 ;
    END
  END SBwest_out[29]
  PIN SBwest_out[2]
    DIRECTION OUTPUT ;
    USE SIGNAL ;
    ANTENNADIFFAREA 0.445500 ;
    PORT
      LAYER met3 ;
        RECT 0.000 223.080 4.000 223.680 ;
    END
  END SBwest_out[2]
  PIN SBwest_out[30]
    DIRECTION OUTPUT ;
    USE SIGNAL ;
    ANTENNADIFFAREA 0.445500 ;
    PORT
      LAYER met3 ;
        RECT 0.000 375.400 4.000 376.000 ;
    END
  END SBwest_out[30]
  PIN SBwest_out[31]
    DIRECTION OUTPUT ;
    USE SIGNAL ;
    ANTENNADIFFAREA 0.445500 ;
    PORT
      LAYER met3 ;
        RECT 0.000 380.840 4.000 381.440 ;
    END
  END SBwest_out[31]
  PIN SBwest_out[3]
    DIRECTION OUTPUT ;
    USE SIGNAL ;
    ANTENNADIFFAREA 0.445500 ;
    PORT
      LAYER met3 ;
        RECT 0.000 228.520 4.000 229.120 ;
    END
  END SBwest_out[3]
  PIN SBwest_out[4]
    DIRECTION OUTPUT ;
    USE SIGNAL ;
    ANTENNADIFFAREA 0.445500 ;
    PORT
      LAYER met3 ;
        RECT 0.000 233.960 4.000 234.560 ;
    END
  END SBwest_out[4]
  PIN SBwest_out[5]
    DIRECTION OUTPUT ;
    USE SIGNAL ;
    ANTENNADIFFAREA 0.445500 ;
    PORT
      LAYER met3 ;
        RECT 0.000 239.400 4.000 240.000 ;
    END
  END SBwest_out[5]
  PIN SBwest_out[6]
    DIRECTION OUTPUT ;
    USE SIGNAL ;
    ANTENNADIFFAREA 0.445500 ;
    PORT
      LAYER met3 ;
        RECT 0.000 244.840 4.000 245.440 ;
    END
  END SBwest_out[6]
  PIN SBwest_out[7]
    DIRECTION OUTPUT ;
    USE SIGNAL ;
    ANTENNADIFFAREA 0.445500 ;
    PORT
      LAYER met3 ;
        RECT 0.000 250.280 4.000 250.880 ;
    END
  END SBwest_out[7]
  PIN SBwest_out[8]
    DIRECTION OUTPUT ;
    USE SIGNAL ;
    ANTENNADIFFAREA 0.445500 ;
    PORT
      LAYER met3 ;
        RECT 0.000 255.720 4.000 256.320 ;
    END
  END SBwest_out[8]
  PIN SBwest_out[9]
    DIRECTION OUTPUT ;
    USE SIGNAL ;
    ANTENNADIFFAREA 0.445500 ;
    PORT
      LAYER met3 ;
        RECT 0.000 261.160 4.000 261.760 ;
    END
  END SBwest_out[9]
  PIN clk
    DIRECTION INPUT ;
    USE SIGNAL ;
    ANTENNAGATEAREA 1.286700 ;
    ANTENNADIFFAREA 0.434700 ;
    PORT
      LAYER met2 ;
        RECT 13.890 396.000 14.170 400.000 ;
    END
  END clk
  PIN config_data_in
    DIRECTION INPUT ;
    USE SIGNAL ;
    ANTENNAGATEAREA 0.631200 ;
    ANTENNADIFFAREA 0.434700 ;
    PORT
      LAYER met2 ;
        RECT 30.450 396.000 30.730 400.000 ;
    END
  END config_data_in
  PIN config_data_out
    DIRECTION OUTPUT ;
    USE SIGNAL ;
    ANTENNADIFFAREA 0.445500 ;
    PORT
      LAYER met3 ;
        RECT 396.000 19.080 400.000 19.680 ;
    END
  END config_data_out
  PIN config_en
    DIRECTION INPUT ;
    USE SIGNAL ;
    ANTENNAGATEAREA 0.647700 ;
    ANTENNADIFFAREA 0.434700 ;
    PORT
      LAYER met2 ;
        RECT 24.930 396.000 25.210 400.000 ;
    END
  END config_en
  PIN le_en
    DIRECTION INPUT ;
    USE SIGNAL ;
    ANTENNAGATEAREA 0.560700 ;
    ANTENNADIFFAREA 0.434700 ;
    PORT
      LAYER met3 ;
        RECT 396.000 24.520 400.000 25.120 ;
    END
  END le_en
  PIN le_nrst
    DIRECTION INPUT ;
    USE SIGNAL ;
    ANTENNAGATEAREA 0.560700 ;
    ANTENNADIFFAREA 0.434700 ;
    PORT
      LAYER met3 ;
        RECT 396.000 29.960 400.000 30.560 ;
    END
  END le_nrst
  PIN nrst
    DIRECTION INPUT ;
    USE SIGNAL ;
    ANTENNAGATEAREA 0.647700 ;
    ANTENNADIFFAREA 0.434700 ;
    PORT
      LAYER met2 ;
        RECT 19.410 396.000 19.690 400.000 ;
    END
  END nrst
  PIN vccd1
    DIRECTION INOUT ;
    USE POWER ;
    PORT
      LAYER met4 ;
        RECT 19.660 5.200 21.260 394.640 ;
    END
    PORT
      LAYER met4 ;
        RECT 173.260 5.200 174.860 394.640 ;
    END
    PORT
      LAYER met4 ;
        RECT 326.860 5.200 328.460 394.640 ;
    END
  END vccd1
  PIN vssd1
    DIRECTION INOUT ;
    USE GROUND ;
    PORT
      LAYER met4 ;
        RECT 22.960 5.200 24.560 394.640 ;
    END
    PORT
      LAYER met4 ;
        RECT 176.560 5.200 178.160 394.640 ;
    END
    PORT
      LAYER met4 ;
        RECT 330.160 5.200 331.760 394.640 ;
    END
  END vssd1
  OBS
      LAYER nwell ;
        RECT 3.950 5.320 395.790 394.590 ;
      LAYER li1 ;
        RECT 4.140 5.355 395.600 394.485 ;
      LAYER met1 ;
        RECT 0.530 2.080 397.830 398.100 ;
      LAYER met2 ;
        RECT 0.550 395.720 13.610 398.130 ;
        RECT 14.450 395.720 19.130 398.130 ;
        RECT 19.970 395.720 24.650 398.130 ;
        RECT 25.490 395.720 30.170 398.130 ;
        RECT 31.010 395.720 35.690 398.130 ;
        RECT 36.530 395.720 41.210 398.130 ;
        RECT 42.050 395.720 46.730 398.130 ;
        RECT 47.570 395.720 52.250 398.130 ;
        RECT 53.090 395.720 57.770 398.130 ;
        RECT 58.610 395.720 63.290 398.130 ;
        RECT 0.550 395.580 63.290 395.720 ;
        RECT 64.130 395.720 68.810 398.130 ;
        RECT 69.650 395.720 74.330 398.130 ;
        RECT 75.170 395.720 79.850 398.130 ;
        RECT 80.690 395.720 85.370 398.130 ;
        RECT 86.210 395.720 90.890 398.130 ;
        RECT 91.730 395.720 96.410 398.130 ;
        RECT 97.250 395.720 101.930 398.130 ;
        RECT 102.770 395.720 107.450 398.130 ;
        RECT 108.290 395.720 112.970 398.130 ;
        RECT 113.810 395.720 118.490 398.130 ;
        RECT 119.330 395.720 124.010 398.130 ;
        RECT 124.850 395.720 129.530 398.130 ;
        RECT 130.370 395.720 135.050 398.130 ;
        RECT 135.890 395.720 140.570 398.130 ;
        RECT 141.410 395.720 146.090 398.130 ;
        RECT 146.930 395.720 151.610 398.130 ;
        RECT 152.450 395.720 157.130 398.130 ;
        RECT 157.970 395.720 162.650 398.130 ;
        RECT 163.490 395.720 168.170 398.130 ;
        RECT 169.010 395.720 173.690 398.130 ;
        RECT 174.530 395.720 179.210 398.130 ;
        RECT 180.050 395.720 184.730 398.130 ;
        RECT 185.570 395.720 190.250 398.130 ;
        RECT 191.090 395.720 195.770 398.130 ;
        RECT 196.610 395.720 201.290 398.130 ;
        RECT 202.130 395.720 206.810 398.130 ;
        RECT 207.650 395.720 212.330 398.130 ;
        RECT 213.170 395.720 217.850 398.130 ;
        RECT 218.690 395.720 223.370 398.130 ;
        RECT 224.210 395.720 228.890 398.130 ;
        RECT 229.730 395.720 234.410 398.130 ;
        RECT 235.250 395.720 239.930 398.130 ;
        RECT 240.770 395.720 245.450 398.130 ;
        RECT 246.290 395.720 250.970 398.130 ;
        RECT 251.810 395.720 256.490 398.130 ;
        RECT 257.330 395.720 262.010 398.130 ;
        RECT 262.850 395.720 267.530 398.130 ;
        RECT 268.370 395.720 273.050 398.130 ;
        RECT 273.890 395.720 278.570 398.130 ;
        RECT 279.410 395.720 284.090 398.130 ;
        RECT 284.930 395.720 289.610 398.130 ;
        RECT 290.450 395.720 295.130 398.130 ;
        RECT 295.970 395.720 300.650 398.130 ;
        RECT 301.490 395.720 306.170 398.130 ;
        RECT 307.010 395.720 311.690 398.130 ;
        RECT 312.530 395.720 317.210 398.130 ;
        RECT 318.050 395.720 322.730 398.130 ;
        RECT 323.570 395.720 328.250 398.130 ;
        RECT 329.090 395.720 333.770 398.130 ;
        RECT 334.610 395.720 339.290 398.130 ;
        RECT 340.130 395.720 344.810 398.130 ;
        RECT 345.650 395.720 350.330 398.130 ;
        RECT 351.170 395.720 355.850 398.130 ;
        RECT 356.690 395.720 361.370 398.130 ;
        RECT 362.210 395.720 366.890 398.130 ;
        RECT 367.730 395.720 372.410 398.130 ;
        RECT 373.250 395.720 377.930 398.130 ;
        RECT 378.770 395.720 383.450 398.130 ;
        RECT 384.290 395.720 397.810 398.130 ;
        RECT 64.130 395.580 397.810 395.720 ;
        RECT 0.550 4.280 397.810 395.580 ;
        RECT 0.550 2.050 35.690 4.280 ;
        RECT 36.530 2.050 41.210 4.280 ;
        RECT 42.050 2.050 46.730 4.280 ;
        RECT 47.570 2.050 52.250 4.280 ;
        RECT 53.090 2.050 57.770 4.280 ;
        RECT 58.610 2.050 63.290 4.280 ;
        RECT 64.130 2.050 68.810 4.280 ;
        RECT 69.650 2.050 74.330 4.280 ;
        RECT 75.170 2.050 79.850 4.280 ;
        RECT 80.690 2.050 85.370 4.280 ;
        RECT 86.210 2.050 90.890 4.280 ;
        RECT 91.730 2.050 96.410 4.280 ;
        RECT 97.250 2.050 101.930 4.280 ;
        RECT 102.770 2.050 107.450 4.280 ;
        RECT 108.290 2.050 112.970 4.280 ;
        RECT 113.810 2.050 118.490 4.280 ;
        RECT 119.330 2.050 124.010 4.280 ;
        RECT 124.850 2.050 129.530 4.280 ;
        RECT 130.370 2.050 135.050 4.280 ;
        RECT 135.890 2.050 140.570 4.280 ;
        RECT 141.410 2.050 146.090 4.280 ;
        RECT 146.930 2.050 151.610 4.280 ;
        RECT 152.450 2.050 157.130 4.280 ;
        RECT 157.970 2.050 162.650 4.280 ;
        RECT 163.490 2.050 168.170 4.280 ;
        RECT 169.010 2.050 173.690 4.280 ;
        RECT 174.530 2.050 179.210 4.280 ;
        RECT 180.050 2.050 184.730 4.280 ;
        RECT 185.570 2.050 190.250 4.280 ;
        RECT 191.090 2.050 195.770 4.280 ;
        RECT 196.610 2.050 201.290 4.280 ;
        RECT 202.130 2.050 206.810 4.280 ;
        RECT 207.650 2.050 212.330 4.280 ;
        RECT 213.170 2.050 217.850 4.280 ;
        RECT 218.690 2.050 223.370 4.280 ;
        RECT 224.210 2.050 228.890 4.280 ;
        RECT 229.730 2.050 234.410 4.280 ;
        RECT 235.250 2.050 239.930 4.280 ;
        RECT 240.770 2.050 245.450 4.280 ;
        RECT 246.290 2.050 250.970 4.280 ;
        RECT 251.810 2.050 256.490 4.280 ;
        RECT 257.330 2.050 262.010 4.280 ;
        RECT 262.850 2.050 267.530 4.280 ;
        RECT 268.370 2.050 273.050 4.280 ;
        RECT 273.890 2.050 278.570 4.280 ;
        RECT 279.410 2.050 284.090 4.280 ;
        RECT 284.930 2.050 289.610 4.280 ;
        RECT 290.450 2.050 295.130 4.280 ;
        RECT 295.970 2.050 300.650 4.280 ;
        RECT 301.490 2.050 306.170 4.280 ;
        RECT 307.010 2.050 311.690 4.280 ;
        RECT 312.530 2.050 317.210 4.280 ;
        RECT 318.050 2.050 322.730 4.280 ;
        RECT 323.570 2.050 328.250 4.280 ;
        RECT 329.090 2.050 333.770 4.280 ;
        RECT 334.610 2.050 339.290 4.280 ;
        RECT 340.130 2.050 344.810 4.280 ;
        RECT 345.650 2.050 350.330 4.280 ;
        RECT 351.170 2.050 355.850 4.280 ;
        RECT 356.690 2.050 361.370 4.280 ;
        RECT 362.210 2.050 366.890 4.280 ;
        RECT 367.730 2.050 372.410 4.280 ;
        RECT 373.250 2.050 377.930 4.280 ;
        RECT 378.770 2.050 383.450 4.280 ;
        RECT 384.290 2.050 397.810 4.280 ;
      LAYER met3 ;
        RECT 0.525 381.840 398.090 394.565 ;
        RECT 4.400 380.440 398.090 381.840 ;
        RECT 0.525 379.120 398.090 380.440 ;
        RECT 0.525 377.720 395.600 379.120 ;
        RECT 0.525 376.400 398.090 377.720 ;
        RECT 4.400 375.000 398.090 376.400 ;
        RECT 0.525 373.680 398.090 375.000 ;
        RECT 0.525 372.280 395.600 373.680 ;
        RECT 0.525 370.960 398.090 372.280 ;
        RECT 4.400 369.560 398.090 370.960 ;
        RECT 0.525 368.240 398.090 369.560 ;
        RECT 0.525 366.840 395.600 368.240 ;
        RECT 0.525 365.520 398.090 366.840 ;
        RECT 4.400 364.120 398.090 365.520 ;
        RECT 0.525 362.800 398.090 364.120 ;
        RECT 0.525 361.400 395.600 362.800 ;
        RECT 0.525 360.080 398.090 361.400 ;
        RECT 4.400 358.680 398.090 360.080 ;
        RECT 0.525 357.360 398.090 358.680 ;
        RECT 0.525 355.960 395.600 357.360 ;
        RECT 0.525 354.640 398.090 355.960 ;
        RECT 4.400 353.240 398.090 354.640 ;
        RECT 0.525 351.920 398.090 353.240 ;
        RECT 0.525 350.520 395.600 351.920 ;
        RECT 0.525 349.200 398.090 350.520 ;
        RECT 4.400 347.800 398.090 349.200 ;
        RECT 0.525 346.480 398.090 347.800 ;
        RECT 0.525 345.080 395.600 346.480 ;
        RECT 0.525 343.760 398.090 345.080 ;
        RECT 4.400 342.360 398.090 343.760 ;
        RECT 0.525 341.040 398.090 342.360 ;
        RECT 0.525 339.640 395.600 341.040 ;
        RECT 0.525 338.320 398.090 339.640 ;
        RECT 4.400 336.920 398.090 338.320 ;
        RECT 0.525 335.600 398.090 336.920 ;
        RECT 0.525 334.200 395.600 335.600 ;
        RECT 0.525 332.880 398.090 334.200 ;
        RECT 4.400 331.480 398.090 332.880 ;
        RECT 0.525 330.160 398.090 331.480 ;
        RECT 0.525 328.760 395.600 330.160 ;
        RECT 0.525 327.440 398.090 328.760 ;
        RECT 4.400 326.040 398.090 327.440 ;
        RECT 0.525 324.720 398.090 326.040 ;
        RECT 0.525 323.320 395.600 324.720 ;
        RECT 0.525 322.000 398.090 323.320 ;
        RECT 4.400 320.600 398.090 322.000 ;
        RECT 0.525 319.280 398.090 320.600 ;
        RECT 0.525 317.880 395.600 319.280 ;
        RECT 0.525 316.560 398.090 317.880 ;
        RECT 4.400 315.160 398.090 316.560 ;
        RECT 0.525 313.840 398.090 315.160 ;
        RECT 0.525 312.440 395.600 313.840 ;
        RECT 0.525 311.120 398.090 312.440 ;
        RECT 4.400 309.720 398.090 311.120 ;
        RECT 0.525 308.400 398.090 309.720 ;
        RECT 0.525 307.000 395.600 308.400 ;
        RECT 0.525 305.680 398.090 307.000 ;
        RECT 4.400 304.280 398.090 305.680 ;
        RECT 0.525 302.960 398.090 304.280 ;
        RECT 0.525 301.560 395.600 302.960 ;
        RECT 0.525 300.240 398.090 301.560 ;
        RECT 4.400 298.840 398.090 300.240 ;
        RECT 0.525 297.520 398.090 298.840 ;
        RECT 0.525 296.120 395.600 297.520 ;
        RECT 0.525 294.800 398.090 296.120 ;
        RECT 4.400 293.400 398.090 294.800 ;
        RECT 0.525 292.080 398.090 293.400 ;
        RECT 0.525 290.680 395.600 292.080 ;
        RECT 0.525 289.360 398.090 290.680 ;
        RECT 4.400 287.960 398.090 289.360 ;
        RECT 0.525 286.640 398.090 287.960 ;
        RECT 0.525 285.240 395.600 286.640 ;
        RECT 0.525 283.920 398.090 285.240 ;
        RECT 4.400 282.520 398.090 283.920 ;
        RECT 0.525 281.200 398.090 282.520 ;
        RECT 0.525 279.800 395.600 281.200 ;
        RECT 0.525 278.480 398.090 279.800 ;
        RECT 4.400 277.080 398.090 278.480 ;
        RECT 0.525 275.760 398.090 277.080 ;
        RECT 0.525 274.360 395.600 275.760 ;
        RECT 0.525 273.040 398.090 274.360 ;
        RECT 4.400 271.640 398.090 273.040 ;
        RECT 0.525 270.320 398.090 271.640 ;
        RECT 0.525 268.920 395.600 270.320 ;
        RECT 0.525 267.600 398.090 268.920 ;
        RECT 4.400 266.200 398.090 267.600 ;
        RECT 0.525 264.880 398.090 266.200 ;
        RECT 0.525 263.480 395.600 264.880 ;
        RECT 0.525 262.160 398.090 263.480 ;
        RECT 4.400 260.760 398.090 262.160 ;
        RECT 0.525 259.440 398.090 260.760 ;
        RECT 0.525 258.040 395.600 259.440 ;
        RECT 0.525 256.720 398.090 258.040 ;
        RECT 4.400 255.320 398.090 256.720 ;
        RECT 0.525 254.000 398.090 255.320 ;
        RECT 0.525 252.600 395.600 254.000 ;
        RECT 0.525 251.280 398.090 252.600 ;
        RECT 4.400 249.880 398.090 251.280 ;
        RECT 0.525 248.560 398.090 249.880 ;
        RECT 0.525 247.160 395.600 248.560 ;
        RECT 0.525 245.840 398.090 247.160 ;
        RECT 4.400 244.440 398.090 245.840 ;
        RECT 0.525 243.120 398.090 244.440 ;
        RECT 0.525 241.720 395.600 243.120 ;
        RECT 0.525 240.400 398.090 241.720 ;
        RECT 4.400 239.000 398.090 240.400 ;
        RECT 0.525 237.680 398.090 239.000 ;
        RECT 0.525 236.280 395.600 237.680 ;
        RECT 0.525 234.960 398.090 236.280 ;
        RECT 4.400 233.560 398.090 234.960 ;
        RECT 0.525 232.240 398.090 233.560 ;
        RECT 0.525 230.840 395.600 232.240 ;
        RECT 0.525 229.520 398.090 230.840 ;
        RECT 4.400 228.120 398.090 229.520 ;
        RECT 0.525 226.800 398.090 228.120 ;
        RECT 0.525 225.400 395.600 226.800 ;
        RECT 0.525 224.080 398.090 225.400 ;
        RECT 4.400 222.680 398.090 224.080 ;
        RECT 0.525 221.360 398.090 222.680 ;
        RECT 0.525 219.960 395.600 221.360 ;
        RECT 0.525 218.640 398.090 219.960 ;
        RECT 4.400 217.240 398.090 218.640 ;
        RECT 0.525 215.920 398.090 217.240 ;
        RECT 0.525 214.520 395.600 215.920 ;
        RECT 0.525 213.200 398.090 214.520 ;
        RECT 4.400 211.800 398.090 213.200 ;
        RECT 0.525 210.480 398.090 211.800 ;
        RECT 0.525 209.080 395.600 210.480 ;
        RECT 0.525 207.760 398.090 209.080 ;
        RECT 4.400 206.360 398.090 207.760 ;
        RECT 0.525 205.040 398.090 206.360 ;
        RECT 0.525 203.640 395.600 205.040 ;
        RECT 0.525 202.320 398.090 203.640 ;
        RECT 4.400 200.920 398.090 202.320 ;
        RECT 0.525 199.600 398.090 200.920 ;
        RECT 0.525 198.200 395.600 199.600 ;
        RECT 0.525 196.880 398.090 198.200 ;
        RECT 4.400 195.480 398.090 196.880 ;
        RECT 0.525 194.160 398.090 195.480 ;
        RECT 0.525 192.760 395.600 194.160 ;
        RECT 0.525 191.440 398.090 192.760 ;
        RECT 4.400 190.040 398.090 191.440 ;
        RECT 0.525 188.720 398.090 190.040 ;
        RECT 0.525 187.320 395.600 188.720 ;
        RECT 0.525 186.000 398.090 187.320 ;
        RECT 4.400 184.600 398.090 186.000 ;
        RECT 0.525 183.280 398.090 184.600 ;
        RECT 0.525 181.880 395.600 183.280 ;
        RECT 0.525 180.560 398.090 181.880 ;
        RECT 4.400 179.160 398.090 180.560 ;
        RECT 0.525 177.840 398.090 179.160 ;
        RECT 0.525 176.440 395.600 177.840 ;
        RECT 0.525 175.120 398.090 176.440 ;
        RECT 4.400 173.720 398.090 175.120 ;
        RECT 0.525 172.400 398.090 173.720 ;
        RECT 0.525 171.000 395.600 172.400 ;
        RECT 0.525 169.680 398.090 171.000 ;
        RECT 4.400 168.280 398.090 169.680 ;
        RECT 0.525 166.960 398.090 168.280 ;
        RECT 0.525 165.560 395.600 166.960 ;
        RECT 0.525 164.240 398.090 165.560 ;
        RECT 4.400 162.840 398.090 164.240 ;
        RECT 0.525 161.520 398.090 162.840 ;
        RECT 0.525 160.120 395.600 161.520 ;
        RECT 0.525 158.800 398.090 160.120 ;
        RECT 4.400 157.400 398.090 158.800 ;
        RECT 0.525 156.080 398.090 157.400 ;
        RECT 0.525 154.680 395.600 156.080 ;
        RECT 0.525 153.360 398.090 154.680 ;
        RECT 4.400 151.960 398.090 153.360 ;
        RECT 0.525 150.640 398.090 151.960 ;
        RECT 0.525 149.240 395.600 150.640 ;
        RECT 0.525 147.920 398.090 149.240 ;
        RECT 4.400 146.520 398.090 147.920 ;
        RECT 0.525 145.200 398.090 146.520 ;
        RECT 0.525 143.800 395.600 145.200 ;
        RECT 0.525 142.480 398.090 143.800 ;
        RECT 4.400 141.080 398.090 142.480 ;
        RECT 0.525 139.760 398.090 141.080 ;
        RECT 0.525 138.360 395.600 139.760 ;
        RECT 0.525 137.040 398.090 138.360 ;
        RECT 4.400 135.640 398.090 137.040 ;
        RECT 0.525 134.320 398.090 135.640 ;
        RECT 0.525 132.920 395.600 134.320 ;
        RECT 0.525 131.600 398.090 132.920 ;
        RECT 4.400 130.200 398.090 131.600 ;
        RECT 0.525 128.880 398.090 130.200 ;
        RECT 0.525 127.480 395.600 128.880 ;
        RECT 0.525 126.160 398.090 127.480 ;
        RECT 4.400 124.760 398.090 126.160 ;
        RECT 0.525 123.440 398.090 124.760 ;
        RECT 0.525 122.040 395.600 123.440 ;
        RECT 0.525 120.720 398.090 122.040 ;
        RECT 4.400 119.320 398.090 120.720 ;
        RECT 0.525 118.000 398.090 119.320 ;
        RECT 0.525 116.600 395.600 118.000 ;
        RECT 0.525 115.280 398.090 116.600 ;
        RECT 4.400 113.880 398.090 115.280 ;
        RECT 0.525 112.560 398.090 113.880 ;
        RECT 0.525 111.160 395.600 112.560 ;
        RECT 0.525 109.840 398.090 111.160 ;
        RECT 4.400 108.440 398.090 109.840 ;
        RECT 0.525 107.120 398.090 108.440 ;
        RECT 0.525 105.720 395.600 107.120 ;
        RECT 0.525 104.400 398.090 105.720 ;
        RECT 4.400 103.000 398.090 104.400 ;
        RECT 0.525 101.680 398.090 103.000 ;
        RECT 0.525 100.280 395.600 101.680 ;
        RECT 0.525 98.960 398.090 100.280 ;
        RECT 4.400 97.560 398.090 98.960 ;
        RECT 0.525 96.240 398.090 97.560 ;
        RECT 0.525 94.840 395.600 96.240 ;
        RECT 0.525 93.520 398.090 94.840 ;
        RECT 4.400 92.120 398.090 93.520 ;
        RECT 0.525 90.800 398.090 92.120 ;
        RECT 0.525 89.400 395.600 90.800 ;
        RECT 0.525 88.080 398.090 89.400 ;
        RECT 4.400 86.680 398.090 88.080 ;
        RECT 0.525 85.360 398.090 86.680 ;
        RECT 0.525 83.960 395.600 85.360 ;
        RECT 0.525 82.640 398.090 83.960 ;
        RECT 4.400 81.240 398.090 82.640 ;
        RECT 0.525 79.920 398.090 81.240 ;
        RECT 0.525 78.520 395.600 79.920 ;
        RECT 0.525 77.200 398.090 78.520 ;
        RECT 4.400 75.800 398.090 77.200 ;
        RECT 0.525 74.480 398.090 75.800 ;
        RECT 0.525 73.080 395.600 74.480 ;
        RECT 0.525 71.760 398.090 73.080 ;
        RECT 4.400 70.360 398.090 71.760 ;
        RECT 0.525 69.040 398.090 70.360 ;
        RECT 0.525 67.640 395.600 69.040 ;
        RECT 0.525 66.320 398.090 67.640 ;
        RECT 4.400 64.920 398.090 66.320 ;
        RECT 0.525 63.600 398.090 64.920 ;
        RECT 0.525 62.200 395.600 63.600 ;
        RECT 0.525 60.880 398.090 62.200 ;
        RECT 4.400 59.480 398.090 60.880 ;
        RECT 0.525 58.160 398.090 59.480 ;
        RECT 0.525 56.760 395.600 58.160 ;
        RECT 0.525 55.440 398.090 56.760 ;
        RECT 4.400 54.040 398.090 55.440 ;
        RECT 0.525 52.720 398.090 54.040 ;
        RECT 0.525 51.320 395.600 52.720 ;
        RECT 0.525 50.000 398.090 51.320 ;
        RECT 4.400 48.600 398.090 50.000 ;
        RECT 0.525 47.280 398.090 48.600 ;
        RECT 0.525 45.880 395.600 47.280 ;
        RECT 0.525 44.560 398.090 45.880 ;
        RECT 4.400 43.160 398.090 44.560 ;
        RECT 0.525 41.840 398.090 43.160 ;
        RECT 0.525 40.440 395.600 41.840 ;
        RECT 0.525 39.120 398.090 40.440 ;
        RECT 4.400 37.720 398.090 39.120 ;
        RECT 0.525 36.400 398.090 37.720 ;
        RECT 0.525 35.000 395.600 36.400 ;
        RECT 0.525 30.960 398.090 35.000 ;
        RECT 0.525 29.560 395.600 30.960 ;
        RECT 0.525 25.520 398.090 29.560 ;
        RECT 0.525 24.120 395.600 25.520 ;
        RECT 0.525 20.080 398.090 24.120 ;
        RECT 0.525 18.680 395.600 20.080 ;
        RECT 0.525 2.215 398.090 18.680 ;
      LAYER met4 ;
        RECT 3.975 4.800 19.260 392.865 ;
        RECT 21.660 4.800 22.560 392.865 ;
        RECT 24.960 4.800 172.860 392.865 ;
        RECT 175.260 4.800 176.160 392.865 ;
        RECT 178.560 4.800 326.460 392.865 ;
        RECT 328.860 4.800 329.760 392.865 ;
        RECT 332.160 4.800 398.065 392.865 ;
        RECT 3.975 2.215 398.065 4.800 ;
  END
END cell4
END LIBRARY

